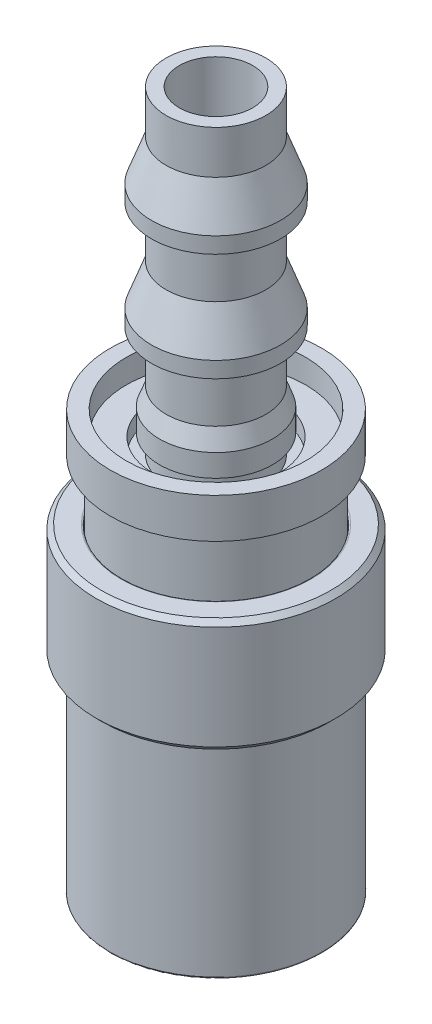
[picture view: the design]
ISO-10303-21;
HEADER;
FILE_DESCRIPTION(('STEP AP214'),'2;1');
FILE_NAME('part.step','',(''),(''),'','','');
FILE_SCHEMA(('AUTOMOTIVE_DESIGN { 1 0 10303 214 1 1 1 1 }'));
ENDSEC;
DATA;
#1=APPLICATION_CONTEXT('core data for automotive mechanical design processes');
#2=APPLICATION_PROTOCOL_DEFINITION('international standard','automotive_design',2000,#1);
#3=PRODUCT_CONTEXT('',#1,'mechanical');
#4=PRODUCT('Part','Part','',(#3));
#5=PRODUCT_RELATED_PRODUCT_CATEGORY('part','',(#4));
#6=PRODUCT_DEFINITION_FORMATION('','',#4);
#7=PRODUCT_DEFINITION_CONTEXT('part definition',#1,'design');
#8=PRODUCT_DEFINITION('design','',#6,#7);
#9=PRODUCT_DEFINITION_SHAPE('','',#8);
#10=(LENGTH_UNIT() NAMED_UNIT(*) SI_UNIT(.MILLI.,.METRE.));
#11=(NAMED_UNIT(*) PLANE_ANGLE_UNIT() SI_UNIT($,.RADIAN.));
#12=(NAMED_UNIT(*) SI_UNIT($,.STERADIAN.) SOLID_ANGLE_UNIT());
#13=UNCERTAINTY_MEASURE_WITH_UNIT(LENGTH_MEASURE(1.E-05),#10,'distance_accuracy_value','');
#14=(GEOMETRIC_REPRESENTATION_CONTEXT(3) GLOBAL_UNCERTAINTY_ASSIGNED_CONTEXT((#13)) GLOBAL_UNIT_ASSIGNED_CONTEXT((#10,
#11,#12)) REPRESENTATION_CONTEXT('',''));
#15=CARTESIAN_POINT('',(0.,0.,0.));
#16=DIRECTION('',(0.,0.,1.));
#17=DIRECTION('',(1.,0.,0.));
#18=AXIS2_PLACEMENT_3D('',#15,#16,#17);
#19=CARTESIAN_POINT('',(0.,31.4198,-8.1915));
#20=DIRECTION('',(0.,1.,0.));
#21=DIRECTION('',(1.,0.,0.));
#22=AXIS2_PLACEMENT_3D('',#19,#20,#21);
#23=PLANE('',#22);
#24=CARTESIAN_POINT('',(0.,31.4198,0.));
#25=DIRECTION('',(0.,-1.,0.));
#26=DIRECTION('',(1.,0.,0.));
#27=AXIS2_PLACEMENT_3D('',#24,#25,#26);
#28=CIRCLE('',#27,5.0165);
#29=CARTESIAN_POINT('',(0.,31.4198,-5.0165));
#30=VERTEX_POINT('',#29);
#31=CARTESIAN_POINT('',(0.,31.4198,5.0165));
#32=VERTEX_POINT('',#31);
#33=EDGE_CURVE('P0_E47',#30,#32,#28,.T.);
#34=ORIENTED_EDGE('',*,*,#33,.T.);
#35=CARTESIAN_POINT('',(0.,31.4198,0.));
#36=DIRECTION('',(0.,-1.,0.));
#37=DIRECTION('',(1.,0.,0.));
#38=AXIS2_PLACEMENT_3D('',#35,#36,#37);
#39=CIRCLE('',#38,5.0165);
#40=EDGE_CURVE('P0_E54',#32,#30,#39,.T.);
#41=ORIENTED_EDGE('',*,*,#40,.T.);
#42=EDGE_LOOP('',(#34,#41));
#43=FACE_BOUND('',#42,.T.);
#44=CARTESIAN_POINT('',(0.,31.4198,0.));
#45=DIRECTION('',(0.,1.,0.));
#46=DIRECTION('',(0.,0.,1.));
#47=AXIS2_PLACEMENT_3D('',#44,#45,#46);
#48=CIRCLE('',#47,7.14375);
#49=CARTESIAN_POINT('',(0.,31.4198,7.14375));
#50=VERTEX_POINT('',#49);
#51=EDGE_CURVE('P0_E11',#50,#50,#48,.F.);
#52=ORIENTED_EDGE('',*,*,#51,.F.);
#53=EDGE_LOOP('',(#52));
#54=FACE_BOUND('',#53,.T.);
#55=ADVANCED_FACE('P0_F16',(#43,#54),#23,.T.);
#56=CARTESIAN_POINT('',(0.,30.1498,-5.0165));
#57=DIRECTION('',(0.,-1.,0.));
#58=DIRECTION('',(0.,0.,-1.));
#59=AXIS2_PLACEMENT_3D('',#56,#57,#58);
#60=PLANE('',#59);
#61=CARTESIAN_POINT('',(0.,30.1498,0.));
#62=DIRECTION('',(0.,-1.,0.));
#63=DIRECTION('',(1.,0.,0.));
#64=AXIS2_PLACEMENT_3D('',#61,#62,#63);
#65=CIRCLE('',#64,5.0165);
#66=CARTESIAN_POINT('',(0.,30.1498,-5.0165));
#67=VERTEX_POINT('',#66);
#68=CARTESIAN_POINT('',(0.,30.1498,5.0165));
#69=VERTEX_POINT('',#68);
#70=EDGE_CURVE('P0_E25',#67,#69,#65,.T.);
#71=ORIENTED_EDGE('',*,*,#70,.F.);
#72=CARTESIAN_POINT('',(0.,30.1498,0.));
#73=DIRECTION('',(0.,-1.,0.));
#74=DIRECTION('',(1.,0.,0.));
#75=AXIS2_PLACEMENT_3D('',#72,#73,#74);
#76=CIRCLE('',#75,5.0165);
#77=EDGE_CURVE('P0_E56',#69,#67,#76,.T.);
#78=ORIENTED_EDGE('',*,*,#77,.F.);
#79=EDGE_LOOP('',(#71,#78));
#80=FACE_BOUND('',#79,.T.);
#81=CARTESIAN_POINT('',(0.,30.1498,0.));
#82=DIRECTION('',(0.,1.,0.));
#83=DIRECTION('',(0.,0.,1.));
#84=AXIS2_PLACEMENT_3D('',#81,#82,#83);
#85=CIRCLE('',#84,8.41375);
#86=CARTESIAN_POINT('',(0.,30.1498,8.41375));
#87=VERTEX_POINT('',#86);
#88=EDGE_CURVE('P0_E63',#87,#87,#85,.T.);
#89=ORIENTED_EDGE('',*,*,#88,.F.);
#90=EDGE_LOOP('',(#89));
#91=FACE_BOUND('',#90,.T.);
#92=ADVANCED_FACE('P0_F96',(#80,#91),#60,.T.);
#93=CARTESIAN_POINT('',(0.,30.7848,0.));
#94=DIRECTION('',(0.,-1.,0.));
#95=DIRECTION('',(0.,0.,-1.));
#96=AXIS2_PLACEMENT_3D('',#93,#94,#95);
#97=CYLINDRICAL_SURFACE('',#96,5.0165);
#98=ORIENTED_EDGE('',*,*,#70,.T.);
#99=DIRECTION('',(0.,1.,0.));
#100=VECTOR('',#99,1.);
#101=CARTESIAN_POINT('',(0.,30.7848,5.0165));
#102=LINE('',#101,#100);
#103=EDGE_CURVE('P0_E59',#69,#32,#102,.T.);
#104=ORIENTED_EDGE('',*,*,#103,.T.);
#105=ORIENTED_EDGE('',*,*,#33,.F.);
#106=ORIENTED_EDGE('',*,*,#40,.F.);
#107=ORIENTED_EDGE('',*,*,#103,.F.);
#108=ORIENTED_EDGE('',*,*,#77,.T.);
#109=EDGE_LOOP('',(#98,#104,#105,#106,#107,#108));
#110=FACE_BOUND('',#109,.T.);
#111=ADVANCED_FACE('P0_F18',(#110),#97,.F.);
#112=CARTESIAN_POINT('',(0.,37.4364687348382,0.));
#113=DIRECTION('',(0.,1.,0.));
#114=DIRECTION('',(0.,0.,1.));
#115=AXIS2_PLACEMENT_3D('',#112,#113,#114);
#116=CYLINDRICAL_SURFACE('',#115,8.41375);
#117=ORIENTED_EDGE('',*,*,#88,.T.);
#118=EDGE_LOOP('',(#117));
#119=FACE_BOUND('',#118,.T.);
#120=CARTESIAN_POINT('',(0.,33.3248,0.));
#121=DIRECTION('',(0.,1.,0.));
#122=DIRECTION('',(0.,0.,1.));
#123=AXIS2_PLACEMENT_3D('',#120,#121,#122);
#124=CIRCLE('',#123,8.41375);
#125=CARTESIAN_POINT('',(0.,33.3248,8.41375));
#126=VERTEX_POINT('',#125);
#127=EDGE_CURVE('P0_E67',#126,#126,#124,.T.);
#128=ORIENTED_EDGE('',*,*,#127,.F.);
#129=EDGE_LOOP('',(#128));
#130=FACE_BOUND('',#129,.T.);
#131=ADVANCED_FACE('P0_F84',(#119,#130),#116,.T.);
#132=CARTESIAN_POINT('',(-8.41375,33.3248,0.));
#133=DIRECTION('',(0.,1.,0.));
#134=DIRECTION('',(0.,0.,1.));
#135=AXIS2_PLACEMENT_3D('',#132,#133,#134);
#136=PLANE('',#135);
#137=ORIENTED_EDGE('',*,*,#127,.T.);
#138=EDGE_LOOP('',(#137));
#139=FACE_BOUND('',#138,.T.);
#140=CARTESIAN_POINT('',(0.,33.3248,0.));
#141=DIRECTION('',(0.,1.,0.));
#142=DIRECTION('',(0.,0.,1.));
#143=AXIS2_PLACEMENT_3D('',#140,#141,#142);
#144=CIRCLE('',#143,7.14375);
#145=CARTESIAN_POINT('',(0.,33.3248,7.14375));
#146=VERTEX_POINT('',#145);
#147=EDGE_CURVE('P0_E75',#146,#146,#144,.T.);
#148=ORIENTED_EDGE('',*,*,#147,.F.);
#149=EDGE_LOOP('',(#148));
#150=FACE_BOUND('',#149,.T.);
#151=ADVANCED_FACE('P0_F82',(#139,#150),#136,.T.);
#152=CARTESIAN_POINT('',(0.,37.4364687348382,0.));
#153=DIRECTION('',(0.,1.,0.));
#154=DIRECTION('',(0.,0.,1.));
#155=AXIS2_PLACEMENT_3D('',#152,#153,#154);
#156=CYLINDRICAL_SURFACE('',#155,7.14375);
#157=ORIENTED_EDGE('',*,*,#147,.T.);
#158=EDGE_LOOP('',(#157));
#159=FACE_BOUND('',#158,.T.);
#160=ORIENTED_EDGE('',*,*,#51,.T.);
#161=EDGE_LOOP('',(#160));
#162=FACE_BOUND('',#161,.T.);
#163=ADVANCED_FACE('P0_F79',(#159,#162),#156,.F.);
#164=CLOSED_SHELL('',(#55,#92,#111,#131,#151,#163));
#165=MANIFOLD_SOLID_BREP('P0_B1',#164);
#166=CARTESIAN_POINT('',(0.,0.254,0.));
#167=DIRECTION('',(0.,1.,0.));
#168=DIRECTION('',(0.,0.,1.));
#169=AXIS2_PLACEMENT_3D('',#166,#167,#168);
#170=TOROIDAL_SURFACE('',#169,6.096,0.254);
#171=CARTESIAN_POINT('',(0.,0.254,0.));
#172=DIRECTION('',(0.,-1.,0.));
#173=DIRECTION('',(0.,0.,-1.));
#174=AXIS2_PLACEMENT_3D('',#171,#172,#173);
#175=CIRCLE('',#174,6.35);
#176=CARTESIAN_POINT('',(0.,0.254,6.35));
#177=VERTEX_POINT('',#176);
#178=CARTESIAN_POINT('',(0.,0.254,-6.35));
#179=VERTEX_POINT('',#178);
#180=EDGE_CURVE('P1_E11',#177,#179,#175,.T.);
#181=ORIENTED_EDGE('',*,*,#180,.T.);
#182=CARTESIAN_POINT('',(0.,0.254,-6.096));
#183=DIRECTION('',(-1.,0.,0.));
#184=DIRECTION('',(0.,0.,-1.));
#185=AXIS2_PLACEMENT_3D('',#182,#183,#184);
#186=CIRCLE('',#185,0.254);
#187=CARTESIAN_POINT('',(0.,0.,-6.096));
#188=VERTEX_POINT('',#187);
#189=EDGE_CURVE('P1_E27',#179,#188,#186,.T.);
#190=ORIENTED_EDGE('',*,*,#189,.T.);
#191=CARTESIAN_POINT('',(0.,0.,0.));
#192=DIRECTION('',(0.,1.,0.));
#193=DIRECTION('',(0.,0.,-1.));
#194=AXIS2_PLACEMENT_3D('',#191,#192,#193);
#195=CIRCLE('',#194,6.096);
#196=CARTESIAN_POINT('',(0.,0.,6.096));
#197=VERTEX_POINT('',#196);
#198=EDGE_CURVE('P1_E196',#188,#197,#195,.T.);
#199=ORIENTED_EDGE('',*,*,#198,.T.);
#200=CARTESIAN_POINT('',(0.,0.,0.));
#201=DIRECTION('',(0.,1.,0.));
#202=DIRECTION('',(0.,0.,-1.));
#203=AXIS2_PLACEMENT_3D('',#200,#201,#202);
#204=CIRCLE('',#203,6.096);
#205=EDGE_CURVE('P1_E190',#197,#188,#204,.T.);
#206=ORIENTED_EDGE('',*,*,#205,.T.);
#207=ORIENTED_EDGE('',*,*,#189,.F.);
#208=CARTESIAN_POINT('',(0.,0.254,0.));
#209=DIRECTION('',(0.,-1.,0.));
#210=DIRECTION('',(0.,0.,-1.));
#211=AXIS2_PLACEMENT_3D('',#208,#209,#210);
#212=CIRCLE('',#211,6.35);
#213=EDGE_CURVE('P1_E183',#179,#177,#212,.T.);
#214=ORIENTED_EDGE('',*,*,#213,.T.);
#215=EDGE_LOOP('',(#181,#190,#199,#206,#207,#214));
#216=FACE_BOUND('',#215,.T.);
#217=ADVANCED_FACE('P1_F16',(#216),#170,.T.);
#218=CARTESIAN_POINT('',(0.,0.,6.35));
#219=DIRECTION('',(0.,-1.,0.));
#220=DIRECTION('',(0.,0.,-1.));
#221=AXIS2_PLACEMENT_3D('',#218,#219,#220);
#222=PLANE('',#221);
#223=ORIENTED_EDGE('',*,*,#205,.F.);
#224=ORIENTED_EDGE('',*,*,#198,.F.);
#225=EDGE_LOOP('',(#223,#224));
#226=FACE_BOUND('',#225,.T.);
#227=CARTESIAN_POINT('',(0.,0.,0.));
#228=DIRECTION('',(0.,-1.,0.));
#229=DIRECTION('',(0.,0.,-1.));
#230=AXIS2_PLACEMENT_3D('',#227,#228,#229);
#231=CIRCLE('',#230,5.5626);
#232=CARTESIAN_POINT('',(0.,0.,5.5626));
#233=VERTEX_POINT('',#232);
#234=EDGE_CURVE('P1_E20',#233,#233,#231,.T.);
#235=ORIENTED_EDGE('',*,*,#234,.F.);
#236=EDGE_LOOP('',(#235));
#237=FACE_BOUND('',#236,.T.);
#238=ADVANCED_FACE('P1_F396',(#226,#237),#222,.T.);
#239=CARTESIAN_POINT('',(0.,7.62,0.));
#240=DIRECTION('',(0.,1.,0.));
#241=DIRECTION('',(0.,0.,1.));
#242=AXIS2_PLACEMENT_3D('',#239,#240,#241);
#243=CYLINDRICAL_SURFACE('',#242,6.35);
#244=CARTESIAN_POINT('',(0.,15.24,0.));
#245=DIRECTION('',(0.,1.,0.));
#246=DIRECTION('',(1.,0.,0.));
#247=AXIS2_PLACEMENT_3D('',#244,#245,#246);
#248=CIRCLE('',#247,6.35);
#249=CARTESIAN_POINT('',(0.,15.24,6.35));
#250=VERTEX_POINT('',#249);
#251=CARTESIAN_POINT('',(0.,15.24,-6.35));
#252=VERTEX_POINT('',#251);
#253=EDGE_CURVE('P1_E261',#250,#252,#248,.T.);
#254=ORIENTED_EDGE('',*,*,#253,.F.);
#255=CARTESIAN_POINT('',(0.,15.24,0.));
#256=DIRECTION('',(0.,1.,0.));
#257=DIRECTION('',(1.,0.,0.));
#258=AXIS2_PLACEMENT_3D('',#255,#256,#257);
#259=CIRCLE('',#258,6.35);
#260=EDGE_CURVE('P1_E199',#252,#250,#259,.T.);
#261=ORIENTED_EDGE('',*,*,#260,.F.);
#262=DIRECTION('',(0.,-1.,0.));
#263=VECTOR('',#262,1.);
#264=CARTESIAN_POINT('',(0.,7.62,-6.35));
#265=LINE('',#264,#263);
#266=EDGE_CURVE('P1_E187',#252,#179,#265,.T.);
#267=ORIENTED_EDGE('',*,*,#266,.T.);
#268=ORIENTED_EDGE('',*,*,#180,.F.);
#269=ORIENTED_EDGE('',*,*,#213,.F.);
#270=ORIENTED_EDGE('',*,*,#266,.F.);
#271=EDGE_LOOP('',(#254,#261,#267,#268,#269,#270));
#272=FACE_BOUND('',#271,.T.);
#273=ADVANCED_FACE('P1_F185',(#272),#243,.T.);
#274=CARTESIAN_POINT('',(0.,29.8958,0.));
#275=DIRECTION('',(0.,1.,0.));
#276=DIRECTION('',(0.,0.,1.));
#277=AXIS2_PLACEMENT_3D('',#274,#275,#276);
#278=TOROIDAL_SURFACE('',#277,7.1501,0.254);
#279=CARTESIAN_POINT('',(0.,30.1498,0.));
#280=DIRECTION('',(0.,-1.,0.));
#281=DIRECTION('',(0.,0.,-1.));
#282=AXIS2_PLACEMENT_3D('',#279,#280,#281);
#283=CIRCLE('',#282,7.1501);
#284=CARTESIAN_POINT('',(0.,30.1498,7.1501));
#285=VERTEX_POINT('',#284);
#286=CARTESIAN_POINT('',(0.,30.1498,-7.1501));
#287=VERTEX_POINT('',#286);
#288=EDGE_CURVE('P1_E202',#285,#287,#283,.T.);
#289=ORIENTED_EDGE('',*,*,#288,.T.);
#290=CARTESIAN_POINT('',(0.,29.8958,-7.1501));
#291=DIRECTION('',(-1.,0.,0.));
#292=DIRECTION('',(0.,0.,-1.));
#293=AXIS2_PLACEMENT_3D('',#290,#291,#292);
#294=CIRCLE('',#293,0.254);
#295=CARTESIAN_POINT('',(0.,29.8958,-7.4041));
#296=VERTEX_POINT('',#295);
#297=EDGE_CURVE('P1_E209',#287,#296,#294,.T.);
#298=ORIENTED_EDGE('',*,*,#297,.T.);
#299=CARTESIAN_POINT('',(0.,29.8958,0.));
#300=DIRECTION('',(0.,1.,0.));
#301=DIRECTION('',(0.,0.,-1.));
#302=AXIS2_PLACEMENT_3D('',#299,#300,#301);
#303=CIRCLE('',#302,7.4041);
#304=CARTESIAN_POINT('',(0.,29.8958,7.4041));
#305=VERTEX_POINT('',#304);
#306=EDGE_CURVE('P1_E241',#296,#305,#303,.T.);
#307=ORIENTED_EDGE('',*,*,#306,.T.);
#308=CARTESIAN_POINT('',(0.,29.8958,0.));
#309=DIRECTION('',(0.,1.,0.));
#310=DIRECTION('',(0.,0.,-1.));
#311=AXIS2_PLACEMENT_3D('',#308,#309,#310);
#312=CIRCLE('',#311,7.4041);
#313=EDGE_CURVE('P1_E245',#305,#296,#312,.T.);
#314=ORIENTED_EDGE('',*,*,#313,.T.);
#315=ORIENTED_EDGE('',*,*,#297,.F.);
#316=CARTESIAN_POINT('',(0.,30.1498,0.));
#317=DIRECTION('',(0.,-1.,0.));
#318=DIRECTION('',(0.,0.,-1.));
#319=AXIS2_PLACEMENT_3D('',#316,#317,#318);
#320=CIRCLE('',#319,7.1501);
#321=EDGE_CURVE('P1_E321',#287,#285,#320,.T.);
#322=ORIENTED_EDGE('',*,*,#321,.T.);
#323=EDGE_LOOP('',(#289,#298,#307,#314,#315,#322));
#324=FACE_BOUND('',#323,.T.);
#325=ADVANCED_FACE('P1_F405',(#324),#278,.T.);
#326=CARTESIAN_POINT('',(0.,22.6949,0.));
#327=DIRECTION('',(0.,1.,0.));
#328=DIRECTION('',(0.,0.,1.));
#329=AXIS2_PLACEMENT_3D('',#326,#327,#328);
#330=CYLINDRICAL_SURFACE('',#329,7.4041);
#331=DIRECTION('',(0.,-1.,0.));
#332=VECTOR('',#331,1.);
#333=CARTESIAN_POINT('',(0.,22.6949,-7.4041));
#334=LINE('',#333,#332);
#335=CARTESIAN_POINT('',(0.,28.1939996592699,-7.4041));
#336=VERTEX_POINT('',#335);
#337=EDGE_CURVE('P1_E40',#296,#336,#334,.T.);
#338=ORIENTED_EDGE('',*,*,#337,.T.);
#339=ORIENTED_EDGE('',*,*,#337,.F.);
#340=ORIENTED_EDGE('',*,*,#313,.F.);
#341=ORIENTED_EDGE('',*,*,#306,.F.);
#342=EDGE_LOOP('',(#338,#339,#340,#341));
#343=FACE_BOUND('',#342,.T.);
#344=DIRECTION('',(0.,-1.,0.));
#345=VECTOR('',#344,1.);
#346=CARTESIAN_POINT('',(0.,22.6949,-7.4041));
#347=LINE('',#346,#345);
#348=CARTESIAN_POINT('',(0.,25.3999996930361,-7.4041));
#349=VERTEX_POINT('',#348);
#350=CARTESIAN_POINT('',(0.,15.494,-7.4041));
#351=VERTEX_POINT('',#350);
#352=EDGE_CURVE('P1_E228',#349,#351,#347,.T.);
#353=ORIENTED_EDGE('',*,*,#352,.F.);
#354=ORIENTED_EDGE('',*,*,#352,.T.);
#355=CARTESIAN_POINT('',(0.,15.494,0.));
#356=DIRECTION('',(0.,-1.,0.));
#357=DIRECTION('',(0.,0.,-1.));
#358=AXIS2_PLACEMENT_3D('',#355,#356,#357);
#359=CIRCLE('',#358,7.4041);
#360=CARTESIAN_POINT('',(0.,15.494,7.4041));
#361=VERTEX_POINT('',#360);
#362=EDGE_CURVE('P1_E224',#361,#351,#359,.T.);
#363=ORIENTED_EDGE('',*,*,#362,.F.);
#364=CARTESIAN_POINT('',(0.,15.494,0.));
#365=DIRECTION('',(0.,-1.,0.));
#366=DIRECTION('',(0.,0.,-1.));
#367=AXIS2_PLACEMENT_3D('',#364,#365,#366);
#368=CIRCLE('',#367,7.4041);
#369=EDGE_CURVE('P1_E235',#351,#361,#368,.T.);
#370=ORIENTED_EDGE('',*,*,#369,.F.);
#371=EDGE_LOOP('',(#353,#354,#363,#370));
#372=FACE_BOUND('',#371,.T.);
#373=ADVANCED_FACE('P1_F440',(#343,#372),#330,.T.);
#374=CARTESIAN_POINT('',(0.,30.1498,4.9784));
#375=DIRECTION('',(0.,1.,0.));
#376=DIRECTION('',(1.,0.,0.));
#377=AXIS2_PLACEMENT_3D('',#374,#375,#376);
#378=PLANE('',#377);
#379=ORIENTED_EDGE('',*,*,#288,.F.);
#380=ORIENTED_EDGE('',*,*,#321,.F.);
#381=EDGE_LOOP('',(#379,#380));
#382=FACE_BOUND('',#381,.T.);
#383=CARTESIAN_POINT('',(0.,30.1498,0.));
#384=DIRECTION('',(0.,1.,0.));
#385=DIRECTION('',(-1.,0.,0.));
#386=AXIS2_PLACEMENT_3D('',#383,#384,#385);
#387=CIRCLE('',#386,3.96875);
#388=CARTESIAN_POINT('',(-3.96875,30.1498,0.));
#389=VERTEX_POINT('',#388);
#390=EDGE_CURVE('P1_E770',#389,#389,#387,.T.);
#391=ORIENTED_EDGE('',*,*,#390,.F.);
#392=EDGE_LOOP('',(#391));
#393=FACE_BOUND('',#392,.T.);
#394=ADVANCED_FACE('P1_F443',(#382,#393),#378,.T.);
#395=CARTESIAN_POINT('',(0.,15.494,0.));
#396=DIRECTION('',(0.,1.,0.));
#397=DIRECTION('',(0.,0.,1.));
#398=AXIS2_PLACEMENT_3D('',#395,#396,#397);
#399=TOROIDAL_SURFACE('',#398,7.1501,0.254);
#400=ORIENTED_EDGE('',*,*,#362,.T.);
#401=CARTESIAN_POINT('',(0.,15.494,-7.1501));
#402=DIRECTION('',(-1.,0.,0.));
#403=DIRECTION('',(0.,0.,-1.));
#404=AXIS2_PLACEMENT_3D('',#401,#402,#403);
#405=CIRCLE('',#404,0.254);
#406=CARTESIAN_POINT('',(0.,15.24,-7.1501));
#407=VERTEX_POINT('',#406);
#408=EDGE_CURVE('P1_E229',#351,#407,#405,.T.);
#409=ORIENTED_EDGE('',*,*,#408,.T.);
#410=CARTESIAN_POINT('',(0.,15.24,0.));
#411=DIRECTION('',(0.,1.,0.));
#412=DIRECTION('',(0.,0.,-1.));
#413=AXIS2_PLACEMENT_3D('',#410,#411,#412);
#414=CIRCLE('',#413,7.1501);
#415=CARTESIAN_POINT('',(0.,15.24,7.1501));
#416=VERTEX_POINT('',#415);
#417=EDGE_CURVE('P1_E234',#407,#416,#414,.T.);
#418=ORIENTED_EDGE('',*,*,#417,.T.);
#419=CARTESIAN_POINT('',(0.,15.24,0.));
#420=DIRECTION('',(0.,1.,0.));
#421=DIRECTION('',(0.,0.,-1.));
#422=AXIS2_PLACEMENT_3D('',#419,#420,#421);
#423=CIRCLE('',#422,7.1501);
#424=EDGE_CURVE('P1_E230',#416,#407,#423,.T.);
#425=ORIENTED_EDGE('',*,*,#424,.T.);
#426=ORIENTED_EDGE('',*,*,#408,.F.);
#427=ORIENTED_EDGE('',*,*,#369,.T.);
#428=EDGE_LOOP('',(#400,#409,#418,#425,#426,#427));
#429=FACE_BOUND('',#428,.T.);
#430=ADVANCED_FACE('P1_F444',(#429),#399,.T.);
#431=CARTESIAN_POINT('',(0.,15.24,7.4041));
#432=DIRECTION('',(0.,-1.,0.));
#433=DIRECTION('',(0.,0.,-1.));
#434=AXIS2_PLACEMENT_3D('',#431,#432,#433);
#435=PLANE('',#434);
#436=ORIENTED_EDGE('',*,*,#424,.F.);
#437=ORIENTED_EDGE('',*,*,#417,.F.);
#438=EDGE_LOOP('',(#436,#437));
#439=FACE_BOUND('',#438,.T.);
#440=ORIENTED_EDGE('',*,*,#253,.T.);
#441=ORIENTED_EDGE('',*,*,#260,.T.);
#442=EDGE_LOOP('',(#440,#441));
#443=FACE_BOUND('',#442,.T.);
#444=ADVANCED_FACE('P1_F18',(#439,#443),#435,.T.);
#445=CARTESIAN_POINT('',(0.,0.3937,0.));
#446=DIRECTION('',(0.,-1.,0.));
#447=DIRECTION('',(0.,0.,-1.));
#448=AXIS2_PLACEMENT_3D('',#445,#446,#447);
#449=CONICAL_SURFACE('',#448,5.1689,0.785398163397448);
#450=ORIENTED_EDGE('',*,*,#234,.T.);
#451=DIRECTION('',(0.,0.707106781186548,-0.707106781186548));
#452=VECTOR('',#451,1.);
#453=CARTESIAN_POINT('',(0.,0.3937,5.1689));
#454=LINE('',#453,#452);
#455=CARTESIAN_POINT('',(0.,0.7874,4.7752));
#456=VERTEX_POINT('',#455);
#457=EDGE_CURVE('P1_E316',#233,#456,#454,.T.);
#458=ORIENTED_EDGE('',*,*,#457,.T.);
#459=CARTESIAN_POINT('',(0.,0.7874,0.));
#460=DIRECTION('',(0.,1.,0.));
#461=DIRECTION('',(0.,0.,-1.));
#462=AXIS2_PLACEMENT_3D('',#459,#460,#461);
#463=CIRCLE('',#462,4.7752);
#464=CARTESIAN_POINT('',(0.,0.7874,-4.7752));
#465=VERTEX_POINT('',#464);
#466=EDGE_CURVE('P1_E311',#456,#465,#463,.T.);
#467=ORIENTED_EDGE('',*,*,#466,.T.);
#468=CARTESIAN_POINT('',(0.,0.7874,0.));
#469=DIRECTION('',(0.,1.,0.));
#470=DIRECTION('',(0.,0.,-1.));
#471=AXIS2_PLACEMENT_3D('',#468,#469,#470);
#472=CIRCLE('',#471,4.7752);
#473=EDGE_CURVE('P1_E307',#465,#456,#472,.T.);
#474=ORIENTED_EDGE('',*,*,#473,.T.);
#475=ORIENTED_EDGE('',*,*,#457,.F.);
#476=EDGE_LOOP('',(#450,#458,#467,#474,#475));
#477=FACE_BOUND('',#476,.T.);
#478=ADVANCED_FACE('P1_F393',(#477),#449,.F.);
#479=CARTESIAN_POINT('',(0.,4.05954416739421,0.));
#480=DIRECTION('',(0.,1.,0.));
#481=DIRECTION('',(0.,0.,1.));
#482=AXIS2_PLACEMENT_3D('',#479,#480,#481);
#483=CYLINDRICAL_SURFACE('',#482,4.7752);
#484=CARTESIAN_POINT('',(0.,8.11908833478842,0.));
#485=DIRECTION('',(0.,1.,0.));
#486=DIRECTION('',(1.,0.,0.));
#487=AXIS2_PLACEMENT_3D('',#484,#485,#486);
#488=CIRCLE('',#487,4.7752);
#489=CARTESIAN_POINT('',(0.,8.11908833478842,4.7752));
#490=VERTEX_POINT('',#489);
#491=CARTESIAN_POINT('',(0.,8.11908833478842,-4.7752));
#492=VERTEX_POINT('',#491);
#493=EDGE_CURVE('P1_E312',#490,#492,#488,.T.);
#494=ORIENTED_EDGE('',*,*,#493,.T.);
#495=DIRECTION('',(0.,-1.,0.));
#496=VECTOR('',#495,1.);
#497=CARTESIAN_POINT('',(0.,4.05954416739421,-4.7752));
#498=LINE('',#497,#496);
#499=EDGE_CURVE('P1_E213',#492,#465,#498,.T.);
#500=ORIENTED_EDGE('',*,*,#499,.T.);
#501=ORIENTED_EDGE('',*,*,#466,.F.);
#502=ORIENTED_EDGE('',*,*,#473,.F.);
#503=ORIENTED_EDGE('',*,*,#499,.F.);
#504=CARTESIAN_POINT('',(0.,8.11908833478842,0.));
#505=DIRECTION('',(0.,1.,0.));
#506=DIRECTION('',(1.,0.,0.));
#507=AXIS2_PLACEMENT_3D('',#504,#505,#506);
#508=CIRCLE('',#507,4.7752);
#509=EDGE_CURVE('P1_E248',#492,#490,#508,.T.);
#510=ORIENTED_EDGE('',*,*,#509,.T.);
#511=EDGE_LOOP('',(#494,#500,#501,#502,#503,#510));
#512=FACE_BOUND('',#511,.T.);
#513=ADVANCED_FACE('P1_F418',(#512),#483,.F.);
#514=CARTESIAN_POINT('',(0.,12.2174,0.));
#515=DIRECTION('',(0.,1.,0.));
#516=DIRECTION('',(0.,0.,1.));
#517=AXIS2_PLACEMENT_3D('',#514,#515,#516);
#518=CYLINDRICAL_SURFACE('',#517,5.0546);
#519=CARTESIAN_POINT('',(0.,12.8524,0.));
#520=DIRECTION('',(0.,1.,0.));
#521=DIRECTION('',(1.,0.,0.));
#522=AXIS2_PLACEMENT_3D('',#519,#520,#521);
#523=CIRCLE('',#522,5.0546);
#524=CARTESIAN_POINT('',(0.,12.8524,5.0546));
#525=VERTEX_POINT('',#524);
#526=CARTESIAN_POINT('',(0.,12.8524,-5.0546));
#527=VERTEX_POINT('',#526);
#528=EDGE_CURVE('P1_E223',#525,#527,#523,.T.);
#529=ORIENTED_EDGE('',*,*,#528,.T.);
#530=DIRECTION('',(0.,-1.,0.));
#531=VECTOR('',#530,1.);
#532=CARTESIAN_POINT('',(0.,12.2174,-5.0546));
#533=LINE('',#532,#531);
#534=CARTESIAN_POINT('',(0.,11.5824,-5.0546));
#535=VERTEX_POINT('',#534);
#536=EDGE_CURVE('P1_E218',#527,#535,#533,.T.);
#537=ORIENTED_EDGE('',*,*,#536,.T.);
#538=CARTESIAN_POINT('',(0.,11.5824,0.));
#539=DIRECTION('',(0.,1.,0.));
#540=DIRECTION('',(1.,0.,0.));
#541=AXIS2_PLACEMENT_3D('',#538,#539,#540);
#542=CIRCLE('',#541,5.0546);
#543=CARTESIAN_POINT('',(0.,11.5824,5.0546));
#544=VERTEX_POINT('',#543);
#545=EDGE_CURVE('P1_E219',#544,#535,#542,.T.);
#546=ORIENTED_EDGE('',*,*,#545,.F.);
#547=CARTESIAN_POINT('',(0.,11.5824,0.));
#548=DIRECTION('',(0.,1.,0.));
#549=DIRECTION('',(1.,0.,0.));
#550=AXIS2_PLACEMENT_3D('',#547,#548,#549);
#551=CIRCLE('',#550,5.0546);
#552=EDGE_CURVE('P1_E240',#535,#544,#551,.T.);
#553=ORIENTED_EDGE('',*,*,#552,.F.);
#554=ORIENTED_EDGE('',*,*,#536,.F.);
#555=CARTESIAN_POINT('',(0.,12.8524,0.));
#556=DIRECTION('',(0.,1.,0.));
#557=DIRECTION('',(1.,0.,0.));
#558=AXIS2_PLACEMENT_3D('',#555,#556,#557);
#559=CIRCLE('',#558,5.0546);
#560=EDGE_CURVE('P1_E215',#527,#525,#559,.T.);
#561=ORIENTED_EDGE('',*,*,#560,.T.);
#562=EDGE_LOOP('',(#529,#537,#546,#553,#554,#561));
#563=FACE_BOUND('',#562,.T.);
#564=ADVANCED_FACE('P1_F274',(#563),#518,.F.);
#565=CARTESIAN_POINT('',(0.,11.4650824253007,0.));
#566=DIRECTION('',(0.,-1.,0.));
#567=DIRECTION('',(0.,0.,1.));
#568=AXIS2_PLACEMENT_3D('',#565,#566,#567);
#569=CONICAL_SURFACE('',#568,5.2578,1.04719755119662);
#570=ORIENTED_EDGE('',*,*,#545,.T.);
#571=DIRECTION('',(0.,-0.499999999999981,-0.86602540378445));
#572=VECTOR('',#571,1.);
#573=CARTESIAN_POINT('',(0.,11.4650824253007,-5.2578));
#574=LINE('',#573,#572);
#575=CARTESIAN_POINT('',(0.,11.3477648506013,-5.461));
#576=VERTEX_POINT('',#575);
#577=EDGE_CURVE('P1_E236',#535,#576,#574,.T.);
#578=ORIENTED_EDGE('',*,*,#577,.T.);
#579=CARTESIAN_POINT('',(0.,11.3477648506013,0.));
#580=DIRECTION('',(0.,1.,0.));
#581=DIRECTION('',(1.,0.,0.));
#582=AXIS2_PLACEMENT_3D('',#579,#580,#581);
#583=CIRCLE('',#582,5.461);
#584=CARTESIAN_POINT('',(0.,11.3477648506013,5.461));
#585=VERTEX_POINT('',#584);
#586=EDGE_CURVE('P1_E279',#585,#576,#583,.T.);
#587=ORIENTED_EDGE('',*,*,#586,.F.);
#588=CARTESIAN_POINT('',(0.,11.3477648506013,0.));
#589=DIRECTION('',(0.,1.,0.));
#590=DIRECTION('',(1.,0.,0.));
#591=AXIS2_PLACEMENT_3D('',#588,#589,#590);
#592=CIRCLE('',#591,5.461);
#593=EDGE_CURVE('P1_E277',#576,#585,#592,.T.);
#594=ORIENTED_EDGE('',*,*,#593,.F.);
#595=ORIENTED_EDGE('',*,*,#577,.F.);
#596=ORIENTED_EDGE('',*,*,#552,.T.);
#597=EDGE_LOOP('',(#570,#578,#587,#594,#595,#596));
#598=FACE_BOUND('',#597,.T.);
#599=ADVANCED_FACE('P1_F270',(#598),#569,.F.);
#600=CARTESIAN_POINT('',(0.,10.3952648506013,0.));
#601=DIRECTION('',(0.,1.,0.));
#602=DIRECTION('',(0.,0.,1.));
#603=AXIS2_PLACEMENT_3D('',#600,#601,#602);
#604=CYLINDRICAL_SURFACE('',#603,5.461);
#605=ORIENTED_EDGE('',*,*,#586,.T.);
#606=DIRECTION('',(0.,-1.,0.));
#607=VECTOR('',#606,1.);
#608=CARTESIAN_POINT('',(0.,10.3952648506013,-5.461));
#609=LINE('',#608,#607);
#610=CARTESIAN_POINT('',(0.,9.44276485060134,-5.461));
#611=VERTEX_POINT('',#610);
#612=EDGE_CURVE('P1_E282',#576,#611,#609,.T.);
#613=ORIENTED_EDGE('',*,*,#612,.T.);
#614=CARTESIAN_POINT('',(0.,9.44276485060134,0.));
#615=DIRECTION('',(0.,1.,0.));
#616=DIRECTION('',(1.,0.,0.));
#617=AXIS2_PLACEMENT_3D('',#614,#615,#616);
#618=CIRCLE('',#617,5.461);
#619=CARTESIAN_POINT('',(0.,9.44276485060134,5.461));
#620=VERTEX_POINT('',#619);
#621=EDGE_CURVE('P1_E283',#620,#611,#618,.T.);
#622=ORIENTED_EDGE('',*,*,#621,.F.);
#623=CARTESIAN_POINT('',(0.,9.44276485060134,0.));
#624=DIRECTION('',(0.,1.,0.));
#625=DIRECTION('',(1.,0.,0.));
#626=AXIS2_PLACEMENT_3D('',#623,#624,#625);
#627=CIRCLE('',#626,5.461);
#628=EDGE_CURVE('P1_E303',#611,#620,#627,.T.);
#629=ORIENTED_EDGE('',*,*,#628,.F.);
#630=ORIENTED_EDGE('',*,*,#612,.F.);
#631=ORIENTED_EDGE('',*,*,#593,.T.);
#632=EDGE_LOOP('',(#605,#613,#622,#629,#630,#631));
#633=FACE_BOUND('',#632,.T.);
#634=ADVANCED_FACE('P1_F286',(#633),#604,.F.);
#635=CARTESIAN_POINT('',(0.,9.325447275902,0.));
#636=DIRECTION('',(0.,1.,0.));
#637=DIRECTION('',(0.,0.,1.));
#638=AXIS2_PLACEMENT_3D('',#635,#636,#637);
#639=CONICAL_SURFACE('',#638,5.2578,1.04719755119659);
#640=ORIENTED_EDGE('',*,*,#621,.T.);
#641=DIRECTION('',(0.,-0.500000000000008,0.866025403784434));
#642=VECTOR('',#641,1.);
#643=CARTESIAN_POINT('',(0.,9.325447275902,-5.2578));
#644=LINE('',#643,#642);
#645=CARTESIAN_POINT('',(0.,9.20812970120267,-5.0546));
#646=VERTEX_POINT('',#645);
#647=EDGE_CURVE('P1_E339',#611,#646,#644,.T.);
#648=ORIENTED_EDGE('',*,*,#647,.T.);
#649=CARTESIAN_POINT('',(0.,9.20812970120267,0.));
#650=DIRECTION('',(0.,1.,0.));
#651=DIRECTION('',(1.,0.,0.));
#652=AXIS2_PLACEMENT_3D('',#649,#650,#651);
#653=CIRCLE('',#652,5.0546);
#654=CARTESIAN_POINT('',(0.,9.20812970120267,5.0546));
#655=VERTEX_POINT('',#654);
#656=EDGE_CURVE('P1_E300',#655,#646,#653,.T.);
#657=ORIENTED_EDGE('',*,*,#656,.F.);
#658=CARTESIAN_POINT('',(0.,9.20812970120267,0.));
#659=DIRECTION('',(0.,1.,0.));
#660=DIRECTION('',(1.,0.,0.));
#661=AXIS2_PLACEMENT_3D('',#658,#659,#660);
#662=CIRCLE('',#661,5.0546);
#663=EDGE_CURVE('P1_E330',#646,#655,#662,.T.);
#664=ORIENTED_EDGE('',*,*,#663,.F.);
#665=ORIENTED_EDGE('',*,*,#647,.F.);
#666=ORIENTED_EDGE('',*,*,#628,.T.);
#667=EDGE_LOOP('',(#640,#648,#657,#664,#665,#666));
#668=FACE_BOUND('',#667,.T.);
#669=ADVANCED_FACE('P1_F456',(#668),#639,.F.);
#670=CARTESIAN_POINT('',(0.,8.74426485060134,0.));
#671=DIRECTION('',(0.,1.,0.));
#672=DIRECTION('',(0.,0.,1.));
#673=AXIS2_PLACEMENT_3D('',#670,#671,#672);
#674=CYLINDRICAL_SURFACE('',#673,5.0546);
#675=ORIENTED_EDGE('',*,*,#656,.T.);
#676=DIRECTION('',(0.,-1.,0.));
#677=VECTOR('',#676,1.);
#678=CARTESIAN_POINT('',(0.,8.74426485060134,-5.0546));
#679=LINE('',#678,#677);
#680=CARTESIAN_POINT('',(0.,8.2804,-5.0546));
#681=VERTEX_POINT('',#680);
#682=EDGE_CURVE('P1_E304',#646,#681,#679,.T.);
#683=ORIENTED_EDGE('',*,*,#682,.T.);
#684=CARTESIAN_POINT('',(0.,8.2804,0.));
#685=DIRECTION('',(0.,1.,0.));
#686=DIRECTION('',(1.,0.,0.));
#687=AXIS2_PLACEMENT_3D('',#684,#685,#686);
#688=CIRCLE('',#687,5.0546);
#689=CARTESIAN_POINT('',(0.,8.2804,5.0546));
#690=VERTEX_POINT('',#689);
#691=EDGE_CURVE('P1_E147',#690,#681,#688,.T.);
#692=ORIENTED_EDGE('',*,*,#691,.F.);
#693=CARTESIAN_POINT('',(0.,8.2804,0.));
#694=DIRECTION('',(0.,1.,0.));
#695=DIRECTION('',(1.,0.,0.));
#696=AXIS2_PLACEMENT_3D('',#693,#694,#695);
#697=CIRCLE('',#696,5.0546);
#698=EDGE_CURVE('P1_E155',#681,#690,#697,.T.);
#699=ORIENTED_EDGE('',*,*,#698,.F.);
#700=ORIENTED_EDGE('',*,*,#682,.F.);
#701=ORIENTED_EDGE('',*,*,#663,.T.);
#702=EDGE_LOOP('',(#675,#683,#692,#699,#700,#701));
#703=FACE_BOUND('',#702,.T.);
#704=ADVANCED_FACE('P1_F458',(#703),#674,.F.);
#705=CARTESIAN_POINT('',(0.,8.19974416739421,0.));
#706=DIRECTION('',(0.,1.,0.));
#707=DIRECTION('',(0.,0.,1.));
#708=AXIS2_PLACEMENT_3D('',#705,#706,#707);
#709=CONICAL_SURFACE('',#708,4.9149,1.04719755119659);
#710=ORIENTED_EDGE('',*,*,#691,.T.);
#711=DIRECTION('',(0.,-0.5,0.866025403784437));
#712=VECTOR('',#711,1.);
#713=CARTESIAN_POINT('',(0.,8.19974416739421,-4.9149));
#714=LINE('',#713,#712);
#715=EDGE_CURVE('P1_E263',#681,#492,#714,.T.);
#716=ORIENTED_EDGE('',*,*,#715,.T.);
#717=ORIENTED_EDGE('',*,*,#493,.F.);
#718=ORIENTED_EDGE('',*,*,#509,.F.);
#719=ORIENTED_EDGE('',*,*,#715,.F.);
#720=ORIENTED_EDGE('',*,*,#698,.T.);
#721=EDGE_LOOP('',(#710,#716,#717,#718,#719,#720));
#722=FACE_BOUND('',#721,.T.);
#723=ADVANCED_FACE('P1_F410',(#722),#709,.F.);
#724=CARTESIAN_POINT('',(0.,19.9136,0.));
#725=DIRECTION('',(0.,1.,0.));
#726=DIRECTION('',(0.,0.,1.));
#727=AXIS2_PLACEMENT_3D('',#724,#725,#726);
#728=CYLINDRICAL_SURFACE('',#727,3.3782);
#729=CARTESIAN_POINT('',(0.,26.9748,0.));
#730=DIRECTION('',(0.,1.,0.));
#731=DIRECTION('',(1.,0.,0.));
#732=AXIS2_PLACEMENT_3D('',#729,#730,#731);
#733=CIRCLE('',#732,3.3782);
#734=CARTESIAN_POINT('',(0.,26.9748,-3.3782));
#735=VERTEX_POINT('',#734);
#736=EDGE_CURVE('P1_E254',#735,#735,#733,.T.);
#737=ORIENTED_EDGE('',*,*,#736,.T.);
#738=DIRECTION('',(0.,-1.,0.));
#739=VECTOR('',#738,1.);
#740=CARTESIAN_POINT('',(0.,19.9136,-3.3782));
#741=LINE('',#740,#739);
#742=CARTESIAN_POINT('',(0.,12.8524,-3.3782));
#743=VERTEX_POINT('',#742);
#744=EDGE_CURVE('P1_E250',#735,#743,#741,.T.);
#745=ORIENTED_EDGE('',*,*,#744,.T.);
#746=CARTESIAN_POINT('',(0.,12.8524,0.));
#747=DIRECTION('',(0.,1.,0.));
#748=DIRECTION('',(1.,0.,0.));
#749=AXIS2_PLACEMENT_3D('',#746,#747,#748);
#750=CIRCLE('',#749,3.3782);
#751=CARTESIAN_POINT('',(0.,12.8524,3.3782));
#752=VERTEX_POINT('',#751);
#753=EDGE_CURVE('P1_E255',#752,#743,#750,.T.);
#754=ORIENTED_EDGE('',*,*,#753,.F.);
#755=CARTESIAN_POINT('',(0.,12.8524,0.));
#756=DIRECTION('',(0.,1.,0.));
#757=DIRECTION('',(1.,0.,0.));
#758=AXIS2_PLACEMENT_3D('',#755,#756,#757);
#759=CIRCLE('',#758,3.3782);
#760=EDGE_CURVE('P1_E340',#743,#752,#759,.T.);
#761=ORIENTED_EDGE('',*,*,#760,.F.);
#762=ORIENTED_EDGE('',*,*,#744,.F.);
#763=EDGE_LOOP('',(#737,#745,#754,#761,#762));
#764=FACE_BOUND('',#763,.T.);
#765=ADVANCED_FACE('P1_F412',(#764),#728,.F.);
#766=CARTESIAN_POINT('',(0.,12.8524,5.0546));
#767=DIRECTION('',(0.,-1.,0.));
#768=DIRECTION('',(0.,0.,-1.));
#769=AXIS2_PLACEMENT_3D('',#766,#767,#768);
#770=PLANE('',#769);
#771=ORIENTED_EDGE('',*,*,#528,.F.);
#772=ORIENTED_EDGE('',*,*,#560,.F.);
#773=EDGE_LOOP('',(#771,#772));
#774=FACE_BOUND('',#773,.T.);
#775=ORIENTED_EDGE('',*,*,#753,.T.);
#776=ORIENTED_EDGE('',*,*,#760,.T.);
#777=EDGE_LOOP('',(#775,#776));
#778=FACE_BOUND('',#777,.T.);
#779=ADVANCED_FACE('P1_F415',(#774,#778),#770,.T.);
#780=CARTESIAN_POINT('',(-4.4918465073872,31.7246,0.));
#781=DIRECTION('',(0.,1.,0.));
#782=DIRECTION('',(-1.,0.,0.));
#783=AXIS2_PLACEMENT_3D('',#780,#781,#782);
#784=PLANE('',#783);
#785=CARTESIAN_POINT('',(0.,31.7246,0.));
#786=DIRECTION('',(0.,1.,0.));
#787=DIRECTION('',(-1.,0.,0.));
#788=AXIS2_PLACEMENT_3D('',#785,#786,#787);
#789=CIRCLE('',#788,4.4918465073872);
#790=CARTESIAN_POINT('',(-4.49184650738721,31.7246,0.));
#791=VERTEX_POINT('',#790);
#792=EDGE_CURVE('P1_E776',#791,#791,#789,.T.);
#793=ORIENTED_EDGE('',*,*,#792,.F.);
#794=EDGE_LOOP('',(#793));
#795=FACE_BOUND('',#794,.T.);
#796=CARTESIAN_POINT('',(0.,31.7246,0.));
#797=DIRECTION('',(0.,1.,0.));
#798=DIRECTION('',(-1.,0.,0.));
#799=AXIS2_PLACEMENT_3D('',#796,#797,#798);
#800=CIRCLE('',#799,3.96875);
#801=CARTESIAN_POINT('',(-3.96875,31.7246,0.));
#802=VERTEX_POINT('',#801);
#803=EDGE_CURVE('P1_E772',#802,#802,#800,.T.);
#804=ORIENTED_EDGE('',*,*,#803,.T.);
#805=EDGE_LOOP('',(#804));
#806=FACE_BOUND('',#805,.T.);
#807=ADVANCED_FACE('P1_F431',(#795,#806),#784,.F.);
#808=CARTESIAN_POINT('',(0.,55.5498,0.));
#809=DIRECTION('',(0.,1.,0.));
#810=DIRECTION('',(-1.,0.,0.));
#811=AXIS2_PLACEMENT_3D('',#808,#809,#810);
#812=CYLINDRICAL_SURFACE('',#811,3.96875);
#813=ORIENTED_EDGE('',*,*,#803,.F.);
#814=EDGE_LOOP('',(#813));
#815=FACE_BOUND('',#814,.T.);
#816=ORIENTED_EDGE('',*,*,#390,.T.);
#817=EDGE_LOOP('',(#816));
#818=FACE_BOUND('',#817,.T.);
#819=ADVANCED_FACE('P1_F495',(#815,#818),#812,.T.);
#820=CARTESIAN_POINT('',(0.,55.5498,0.));
#821=DIRECTION('',(0.,1.,0.));
#822=DIRECTION('',(-1.,0.,0.));
#823=AXIS2_PLACEMENT_3D('',#820,#821,#822);
#824=CYLINDRICAL_SURFACE('',#823,4.4918465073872);
#825=CARTESIAN_POINT('',(0.,33.5026,0.));
#826=DIRECTION('',(0.,1.,0.));
#827=DIRECTION('',(-1.,0.,0.));
#828=AXIS2_PLACEMENT_3D('',#825,#826,#827);
#829=CIRCLE('',#828,4.4918465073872);
#830=CARTESIAN_POINT('',(-4.49184650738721,33.5026,0.));
#831=VERTEX_POINT('',#830);
#832=EDGE_CURVE('P1_E785',#831,#831,#829,.T.);
#833=ORIENTED_EDGE('',*,*,#832,.F.);
#834=EDGE_LOOP('',(#833));
#835=FACE_BOUND('',#834,.T.);
#836=ORIENTED_EDGE('',*,*,#792,.T.);
#837=EDGE_LOOP('',(#836));
#838=FACE_BOUND('',#837,.T.);
#839=ADVANCED_FACE('P1_F504',(#835,#838),#824,.T.);
#840=CARTESIAN_POINT('',(0.,33.5026,0.));
#841=DIRECTION('',(0.,-1.,0.));
#842=DIRECTION('',(1.,0.,0.));
#843=AXIS2_PLACEMENT_3D('',#840,#841,#842);
#844=CONICAL_SURFACE('',#843,4.4918465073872,0.348153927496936);
#845=CARTESIAN_POINT('',(0.,34.9438839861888,0.));
#846=DIRECTION('',(0.,1.,0.));
#847=DIRECTION('',(-1.,0.,0.));
#848=AXIS2_PLACEMENT_3D('',#845,#846,#847);
#849=CIRCLE('',#848,3.96875);
#850=CARTESIAN_POINT('',(-3.96875,34.9438839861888,0.));
#851=VERTEX_POINT('',#850);
#852=EDGE_CURVE('P1_E788',#851,#851,#849,.T.);
#853=ORIENTED_EDGE('',*,*,#852,.F.);
#854=EDGE_LOOP('',(#853));
#855=FACE_BOUND('',#854,.T.);
#856=ORIENTED_EDGE('',*,*,#832,.T.);
#857=EDGE_LOOP('',(#856));
#858=FACE_BOUND('',#857,.T.);
#859=ADVANCED_FACE('P1_F513',(#855,#858),#844,.T.);
#860=CARTESIAN_POINT('',(0.,55.5498,0.));
#861=DIRECTION('',(0.,1.,0.));
#862=DIRECTION('',(-1.,0.,0.));
#863=AXIS2_PLACEMENT_3D('',#860,#861,#862);
#864=CYLINDRICAL_SURFACE('',#863,3.96875);
#865=CARTESIAN_POINT('',(0.,39.0398,0.));
#866=DIRECTION('',(0.,1.,0.));
#867=DIRECTION('',(-1.,0.,0.));
#868=AXIS2_PLACEMENT_3D('',#865,#866,#867);
#869=CIRCLE('',#868,3.96875);
#870=CARTESIAN_POINT('',(-3.96875,39.0398,0.));
#871=VERTEX_POINT('',#870);
#872=EDGE_CURVE('P1_E791',#871,#871,#869,.T.);
#873=ORIENTED_EDGE('',*,*,#872,.F.);
#874=EDGE_LOOP('',(#873));
#875=FACE_BOUND('',#874,.T.);
#876=ORIENTED_EDGE('',*,*,#852,.T.);
#877=EDGE_LOOP('',(#876));
#878=FACE_BOUND('',#877,.T.);
#879=ADVANCED_FACE('P1_F522',(#875,#878),#864,.T.);
#880=CARTESIAN_POINT('',(0.,55.5498,0.));
#881=DIRECTION('',(0.,1.,0.));
#882=DIRECTION('',(-1.,0.,0.));
#883=AXIS2_PLACEMENT_3D('',#880,#881,#882);
#884=CYLINDRICAL_SURFACE('',#883,3.96875);
#885=CARTESIAN_POINT('',(0.,52.1051526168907,0.));
#886=DIRECTION('',(0.,1.,0.));
#887=DIRECTION('',(-1.,0.,0.));
#888=AXIS2_PLACEMENT_3D('',#885,#886,#887);
#889=CIRCLE('',#888,3.96875);
#890=CARTESIAN_POINT('',(-3.96875,52.1051526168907,0.));
#891=VERTEX_POINT('',#890);
#892=EDGE_CURVE('P1_E343',#891,#891,#889,.T.);
#893=ORIENTED_EDGE('',*,*,#892,.T.);
#894=EDGE_LOOP('',(#893));
#895=FACE_BOUND('',#894,.T.);
#896=CARTESIAN_POINT('',(0.,55.5498,0.));
#897=DIRECTION('',(0.,1.,0.));
#898=DIRECTION('',(0.,0.,1.));
#899=AXIS2_PLACEMENT_3D('',#896,#897,#898);
#900=CIRCLE('',#899,3.96875);
#901=CARTESIAN_POINT('',(0.,55.5498,3.96875));
#902=VERTEX_POINT('',#901);
#903=EDGE_CURVE('P1_E838',#902,#902,#900,.T.);
#904=ORIENTED_EDGE('',*,*,#903,.F.);
#905=EDGE_LOOP('',(#904));
#906=FACE_BOUND('',#905,.T.);
#907=ADVANCED_FACE('P1_F531',(#895,#906),#884,.T.);
#908=CARTESIAN_POINT('',(0.,48.895,0.));
#909=DIRECTION('',(0.,-1.,0.));
#910=DIRECTION('',(1.,0.,0.));
#911=AXIS2_PLACEMENT_3D('',#908,#909,#910);
#912=CONICAL_SURFACE('',#911,5.13715,0.349065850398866);
#913=ORIENTED_EDGE('',*,*,#892,.F.);
#914=EDGE_LOOP('',(#913));
#915=FACE_BOUND('',#914,.T.);
#916=CARTESIAN_POINT('',(0.,48.895,0.));
#917=DIRECTION('',(0.,1.,0.));
#918=DIRECTION('',(-1.,0.,0.));
#919=AXIS2_PLACEMENT_3D('',#916,#917,#918);
#920=CIRCLE('',#919,5.13715);
#921=CARTESIAN_POINT('',(-5.13715,48.895,0.));
#922=VERTEX_POINT('',#921);
#923=EDGE_CURVE('P1_E809',#922,#922,#920,.T.);
#924=ORIENTED_EDGE('',*,*,#923,.T.);
#925=EDGE_LOOP('',(#924));
#926=FACE_BOUND('',#925,.T.);
#927=ADVANCED_FACE('P1_F540',(#915,#926),#912,.T.);
#928=CARTESIAN_POINT('',(0.,55.5498,0.));
#929=DIRECTION('',(0.,1.,0.));
#930=DIRECTION('',(-1.,0.,0.));
#931=AXIS2_PLACEMENT_3D('',#928,#929,#930);
#932=CYLINDRICAL_SURFACE('',#931,5.13715);
#933=ORIENTED_EDGE('',*,*,#923,.F.);
#934=EDGE_LOOP('',(#933));
#935=FACE_BOUND('',#934,.T.);
#936=CARTESIAN_POINT('',(0.,47.625,0.));
#937=DIRECTION('',(0.,1.,0.));
#938=DIRECTION('',(-1.,0.,0.));
#939=AXIS2_PLACEMENT_3D('',#936,#937,#938);
#940=CIRCLE('',#939,5.13715);
#941=CARTESIAN_POINT('',(-5.13715,47.625,0.));
#942=VERTEX_POINT('',#941);
#943=EDGE_CURVE('P1_E806',#942,#942,#940,.T.);
#944=ORIENTED_EDGE('',*,*,#943,.T.);
#945=EDGE_LOOP('',(#944));
#946=FACE_BOUND('',#945,.T.);
#947=ADVANCED_FACE('P1_F438',(#935,#946),#932,.T.);
#948=CARTESIAN_POINT('',(0.,47.625,5.9182));
#949=DIRECTION('',(0.,-1.,0.));
#950=DIRECTION('',(0.,0.,-1.));
#951=AXIS2_PLACEMENT_3D('',#948,#949,#950);
#952=PLANE('',#951);
#953=ORIENTED_EDGE('',*,*,#943,.F.);
#954=EDGE_LOOP('',(#953));
#955=FACE_BOUND('',#954,.T.);
#956=CARTESIAN_POINT('',(0.,47.625,0.));
#957=DIRECTION('',(0.,1.,0.));
#958=DIRECTION('',(-1.,0.,0.));
#959=AXIS2_PLACEMENT_3D('',#956,#957,#958);
#960=CIRCLE('',#959,3.96875);
#961=CARTESIAN_POINT('',(-3.96875,47.625,0.));
#962=VERTEX_POINT('',#961);
#963=EDGE_CURVE('P1_E803',#962,#962,#960,.T.);
#964=ORIENTED_EDGE('',*,*,#963,.T.);
#965=EDGE_LOOP('',(#964));
#966=FACE_BOUND('',#965,.T.);
#967=ADVANCED_FACE('P1_F434',(#955,#966),#952,.T.);
#968=CARTESIAN_POINT('',(0.,55.5498,0.));
#969=DIRECTION('',(0.,1.,0.));
#970=DIRECTION('',(-1.,0.,0.));
#971=AXIS2_PLACEMENT_3D('',#968,#969,#970);
#972=CYLINDRICAL_SURFACE('',#971,3.96875);
#973=ORIENTED_EDGE('',*,*,#963,.F.);
#974=EDGE_LOOP('',(#973));
#975=FACE_BOUND('',#974,.T.);
#976=CARTESIAN_POINT('',(0.,43.5290839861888,0.));
#977=DIRECTION('',(0.,1.,0.));
#978=DIRECTION('',(-1.,0.,0.));
#979=AXIS2_PLACEMENT_3D('',#976,#977,#978);
#980=CIRCLE('',#979,3.96875);
#981=CARTESIAN_POINT('',(-3.96875,43.5290839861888,0.));
#982=VERTEX_POINT('',#981);
#983=EDGE_CURVE('P1_E800',#982,#982,#980,.T.);
#984=ORIENTED_EDGE('',*,*,#983,.T.);
#985=EDGE_LOOP('',(#984));
#986=FACE_BOUND('',#985,.T.);
#987=ADVANCED_FACE('P1_F437',(#975,#986),#972,.T.);
#988=CARTESIAN_POINT('',(0.,40.3098,0.));
#989=DIRECTION('',(0.,-1.,0.));
#990=DIRECTION('',(1.,0.,0.));
#991=AXIS2_PLACEMENT_3D('',#988,#989,#990);
#992=CONICAL_SURFACE('',#991,5.13715,0.348153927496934);
#993=ORIENTED_EDGE('',*,*,#983,.F.);
#994=EDGE_LOOP('',(#993));
#995=FACE_BOUND('',#994,.T.);
#996=CARTESIAN_POINT('',(0.,40.3098,0.));
#997=DIRECTION('',(0.,1.,0.));
#998=DIRECTION('',(-1.,0.,0.));
#999=AXIS2_PLACEMENT_3D('',#996,#997,#998);
#1000=CIRCLE('',#999,5.13715);
#1001=CARTESIAN_POINT('',(-5.13715,40.3098,0.));
#1002=VERTEX_POINT('',#1001);
#1003=EDGE_CURVE('P1_E797',#1002,#1002,#1000,.T.);
#1004=ORIENTED_EDGE('',*,*,#1003,.T.);
#1005=EDGE_LOOP('',(#1004));
#1006=FACE_BOUND('',#1005,.T.);
#1007=ADVANCED_FACE('P1_F570',(#995,#1006),#992,.T.);
#1008=CARTESIAN_POINT('',(0.,55.5498,0.));
#1009=DIRECTION('',(0.,1.,0.));
#1010=DIRECTION('',(-1.,0.,0.));
#1011=AXIS2_PLACEMENT_3D('',#1008,#1009,#1010);
#1012=CYLINDRICAL_SURFACE('',#1011,5.13715);
#1013=ORIENTED_EDGE('',*,*,#1003,.F.);
#1014=EDGE_LOOP('',(#1013));
#1015=FACE_BOUND('',#1014,.T.);
#1016=CARTESIAN_POINT('',(0.,39.0398,0.));
#1017=DIRECTION('',(0.,1.,0.));
#1018=DIRECTION('',(-1.,0.,0.));
#1019=AXIS2_PLACEMENT_3D('',#1016,#1017,#1018);
#1020=CIRCLE('',#1019,5.13715);
#1021=CARTESIAN_POINT('',(-5.13715,39.0398,0.));
#1022=VERTEX_POINT('',#1021);
#1023=EDGE_CURVE('P1_E794',#1022,#1022,#1020,.T.);
#1024=ORIENTED_EDGE('',*,*,#1023,.T.);
#1025=EDGE_LOOP('',(#1024));
#1026=FACE_BOUND('',#1025,.T.);
#1027=ADVANCED_FACE('P1_F451',(#1015,#1026),#1012,.T.);
#1028=CARTESIAN_POINT('',(0.,39.0398,5.969));
#1029=DIRECTION('',(0.,-1.,0.));
#1030=DIRECTION('',(0.,0.,-1.));
#1031=AXIS2_PLACEMENT_3D('',#1028,#1029,#1030);
#1032=PLANE('',#1031);
#1033=ORIENTED_EDGE('',*,*,#1023,.F.);
#1034=EDGE_LOOP('',(#1033));
#1035=FACE_BOUND('',#1034,.T.);
#1036=ORIENTED_EDGE('',*,*,#872,.T.);
#1037=EDGE_LOOP('',(#1036));
#1038=FACE_BOUND('',#1037,.T.);
#1039=ADVANCED_FACE('P1_F447',(#1035,#1038),#1032,.T.);
#1040=CARTESIAN_POINT('',(0.,26.9748,0.));
#1041=DIRECTION('',(0.,1.,0.));
#1042=DIRECTION('',(0.,0.,1.));
#1043=AXIS2_PLACEMENT_3D('',#1040,#1041,#1042);
#1044=PLANE('',#1043);
#1045=CARTESIAN_POINT('',(0.,26.9748,0.));
#1046=DIRECTION('',(0.,1.,0.));
#1047=DIRECTION('',(0.,0.,1.));
#1048=AXIS2_PLACEMENT_3D('',#1045,#1046,#1047);
#1049=CIRCLE('',#1048,2.921);
#1050=CARTESIAN_POINT('',(0.,26.9748,2.921));
#1051=VERTEX_POINT('',#1050);
#1052=EDGE_CURVE('P1_E779',#1051,#1051,#1049,.T.);
#1053=ORIENTED_EDGE('',*,*,#1052,.T.);
#1054=EDGE_LOOP('',(#1053));
#1055=FACE_BOUND('',#1054,.T.);
#1056=ORIENTED_EDGE('',*,*,#736,.F.);
#1057=EDGE_LOOP('',(#1056));
#1058=FACE_BOUND('',#1057,.T.);
#1059=ADVANCED_FACE('P1_F450',(#1055,#1058),#1044,.F.);
#1060=CARTESIAN_POINT('',(0.,55.5498,0.));
#1061=DIRECTION('',(0.,1.,0.));
#1062=DIRECTION('',(0.,0.,1.));
#1063=AXIS2_PLACEMENT_3D('',#1060,#1061,#1062);
#1064=PLANE('',#1063);
#1065=CARTESIAN_POINT('',(0.,55.5498,0.));
#1066=DIRECTION('',(0.,1.,0.));
#1067=DIRECTION('',(0.,0.,1.));
#1068=AXIS2_PLACEMENT_3D('',#1065,#1066,#1067);
#1069=CIRCLE('',#1068,2.921);
#1070=CARTESIAN_POINT('',(0.,55.5498,2.921));
#1071=VERTEX_POINT('',#1070);
#1072=EDGE_CURVE('P1_E773',#1071,#1071,#1069,.T.);
#1073=ORIENTED_EDGE('',*,*,#1072,.F.);
#1074=EDGE_LOOP('',(#1073));
#1075=FACE_BOUND('',#1074,.T.);
#1076=ORIENTED_EDGE('',*,*,#903,.T.);
#1077=EDGE_LOOP('',(#1076));
#1078=FACE_BOUND('',#1077,.T.);
#1079=ADVANCED_FACE('P1_F600',(#1075,#1078),#1064,.T.);
#1080=CARTESIAN_POINT('',(0.,55.5498,0.));
#1081=DIRECTION('',(0.,-1.,0.));
#1082=DIRECTION('',(0.,0.,-1.));
#1083=AXIS2_PLACEMENT_3D('',#1080,#1081,#1082);
#1084=CYLINDRICAL_SURFACE('',#1083,2.921);
#1085=ORIENTED_EDGE('',*,*,#1072,.T.);
#1086=EDGE_LOOP('',(#1085));
#1087=FACE_BOUND('',#1086,.T.);
#1088=ORIENTED_EDGE('',*,*,#1052,.F.);
#1089=EDGE_LOOP('',(#1088));
#1090=FACE_BOUND('',#1089,.T.);
#1091=ADVANCED_FACE('P1_F609',(#1087,#1090),#1084,.F.);
#1092=CLOSED_SHELL('',(#217,#238,#273,#325,#373,#394,#430,#444,#478,#513,#564,#599,#634,#669,
#704,#723,#765,#779,#807,#819,#839,#859,#879,#907,#927,#947,#967,#987,#1007,#1027,#1039,#1059,
#1079,#1091));
#1093=MANIFOLD_SOLID_BREP('P1_B1',#1092);
#1094=CARTESIAN_POINT('',(0.,25.2095,0.));
#1095=DIRECTION('',(0.,-1.,0.));
#1096=DIRECTION('',(0.,0.,-1.));
#1097=AXIS2_PLACEMENT_3D('',#1094,#1095,#1096);
#1098=CONICAL_SURFACE('',#1097,9.3345,0.785398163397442);
#1099=CARTESIAN_POINT('',(0.,25.4,0.));
#1100=DIRECTION('',(0.,-1.,0.));
#1101=DIRECTION('',(0.,0.,-1.));
#1102=AXIS2_PLACEMENT_3D('',#1099,#1100,#1101);
#1103=CIRCLE('',#1102,9.144);
#1104=CARTESIAN_POINT('',(0.,25.4,9.144));
#1105=VERTEX_POINT('',#1104);
#1106=EDGE_CURVE('P2_E11',#1105,#1105,#1103,.T.);
#1107=ORIENTED_EDGE('',*,*,#1106,.T.);
#1108=DIRECTION('',(0.,-0.707106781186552,0.707106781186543));
#1109=VECTOR('',#1108,1.);
#1110=CARTESIAN_POINT('',(0.,25.2095,9.3345));
#1111=LINE('',#1110,#1109);
#1112=CARTESIAN_POINT('',(0.,25.019,9.525));
#1113=VERTEX_POINT('',#1112);
#1114=EDGE_CURVE('P2_E27',#1105,#1113,#1111,.T.);
#1115=ORIENTED_EDGE('',*,*,#1114,.T.);
#1116=CARTESIAN_POINT('',(0.,25.019,0.));
#1117=DIRECTION('',(0.,1.,0.));
#1118=DIRECTION('',(0.,0.,-1.));
#1119=AXIS2_PLACEMENT_3D('',#1116,#1117,#1118);
#1120=CIRCLE('',#1119,9.525);
#1121=CARTESIAN_POINT('',(0.,25.019,-9.525));
#1122=VERTEX_POINT('',#1121);
#1123=EDGE_CURVE('P2_E168',#1113,#1122,#1120,.T.);
#1124=ORIENTED_EDGE('',*,*,#1123,.T.);
#1125=CARTESIAN_POINT('',(0.,25.019,0.));
#1126=DIRECTION('',(0.,1.,0.));
#1127=DIRECTION('',(0.,0.,-1.));
#1128=AXIS2_PLACEMENT_3D('',#1125,#1126,#1127);
#1129=CIRCLE('',#1128,9.525);
#1130=EDGE_CURVE('P2_E272',#1122,#1113,#1129,.T.);
#1131=ORIENTED_EDGE('',*,*,#1130,.T.);
#1132=ORIENTED_EDGE('',*,*,#1114,.F.);
#1133=EDGE_LOOP('',(#1107,#1115,#1124,#1131,#1132));
#1134=FACE_BOUND('',#1133,.T.);
#1135=ADVANCED_FACE('P2_F16',(#1134),#1098,.T.);
#1136=CARTESIAN_POINT('',(0.,20.828,0.));
#1137=DIRECTION('',(0.,1.,0.));
#1138=DIRECTION('',(0.,0.,1.));
#1139=AXIS2_PLACEMENT_3D('',#1136,#1137,#1138);
#1140=CYLINDRICAL_SURFACE('',#1139,9.525);
#1141=ORIENTED_EDGE('',*,*,#1123,.F.);
#1142=ORIENTED_EDGE('',*,*,#1130,.F.);
#1143=DIRECTION('',(0.,-1.,0.));
#1144=VECTOR('',#1143,1.);
#1145=CARTESIAN_POINT('',(0.,20.828,-9.525));
#1146=LINE('',#1145,#1144);
#1147=CARTESIAN_POINT('',(0.,16.764,-9.525));
#1148=VERTEX_POINT('',#1147);
#1149=EDGE_CURVE('P2_E202',#1122,#1148,#1146,.T.);
#1150=ORIENTED_EDGE('',*,*,#1149,.T.);
#1151=CARTESIAN_POINT('',(0.,16.764,0.));
#1152=DIRECTION('',(0.,-1.,0.));
#1153=DIRECTION('',(0.,0.,-1.));
#1154=AXIS2_PLACEMENT_3D('',#1151,#1152,#1153);
#1155=CIRCLE('',#1154,9.525);
#1156=CARTESIAN_POINT('',(0.,16.764,9.525));
#1157=VERTEX_POINT('',#1156);
#1158=EDGE_CURVE('P2_E146',#1157,#1148,#1155,.T.);
#1159=ORIENTED_EDGE('',*,*,#1158,.F.);
#1160=CARTESIAN_POINT('',(0.,16.764,0.));
#1161=DIRECTION('',(0.,-1.,0.));
#1162=DIRECTION('',(0.,0.,-1.));
#1163=AXIS2_PLACEMENT_3D('',#1160,#1161,#1162);
#1164=CIRCLE('',#1163,9.525);
#1165=EDGE_CURVE('P2_E207',#1148,#1157,#1164,.T.);
#1166=ORIENTED_EDGE('',*,*,#1165,.F.);
#1167=ORIENTED_EDGE('',*,*,#1149,.F.);
#1168=EDGE_LOOP('',(#1141,#1142,#1150,#1159,#1166,#1167));
#1169=FACE_BOUND('',#1168,.T.);
#1170=ADVANCED_FACE('P2_F367',(#1169),#1140,.T.);
#1171=CARTESIAN_POINT('',(0.,25.4,7.4549));
#1172=DIRECTION('',(0.,1.,0.));
#1173=DIRECTION('',(1.,0.,0.));
#1174=AXIS2_PLACEMENT_3D('',#1171,#1172,#1173);
#1175=PLANE('',#1174);
#1176=ORIENTED_EDGE('',*,*,#1106,.F.);
#1177=EDGE_LOOP('',(#1176));
#1178=FACE_BOUND('',#1177,.T.);
#1179=CARTESIAN_POINT('',(0.,25.4,0.));
#1180=DIRECTION('',(0.,1.,0.));
#1181=DIRECTION('',(0.,0.,-1.));
#1182=AXIS2_PLACEMENT_3D('',#1179,#1180,#1181);
#1183=CIRCLE('',#1182,7.5819);
#1184=CARTESIAN_POINT('',(0.,25.4,-7.5819));
#1185=VERTEX_POINT('',#1184);
#1186=EDGE_CURVE('P2_E237',#1185,#1185,#1183,.T.);
#1187=ORIENTED_EDGE('',*,*,#1186,.F.);
#1188=EDGE_LOOP('',(#1187));
#1189=FACE_BOUND('',#1188,.T.);
#1190=ADVANCED_FACE('P2_F373',(#1178,#1189),#1175,.T.);
#1191=CARTESIAN_POINT('',(0.,6.096,0.));
#1192=DIRECTION('',(0.,1.,0.));
#1193=DIRECTION('',(0.,0.,1.));
#1194=AXIS2_PLACEMENT_3D('',#1191,#1192,#1193);
#1195=TOROIDAL_SURFACE('',#1194,6.6802,0.254);
#1196=CARTESIAN_POINT('',(0.,6.096,0.));
#1197=DIRECTION('',(0.,-1.,0.));
#1198=DIRECTION('',(0.,0.,-1.));
#1199=AXIS2_PLACEMENT_3D('',#1196,#1197,#1198);
#1200=CIRCLE('',#1199,6.4262);
#1201=CARTESIAN_POINT('',(0.,6.096,6.4262));
#1202=VERTEX_POINT('',#1201);
#1203=CARTESIAN_POINT('',(0.,6.096,-6.4262));
#1204=VERTEX_POINT('',#1203);
#1205=EDGE_CURVE('P2_E199',#1202,#1204,#1200,.T.);
#1206=ORIENTED_EDGE('',*,*,#1205,.T.);
#1207=CARTESIAN_POINT('',(0.,6.096,-6.6802));
#1208=DIRECTION('',(-1.,0.,0.));
#1209=DIRECTION('',(0.,0.,-1.));
#1210=AXIS2_PLACEMENT_3D('',#1207,#1208,#1209);
#1211=CIRCLE('',#1210,0.254);
#1212=CARTESIAN_POINT('',(0.,6.35,-6.6802));
#1213=VERTEX_POINT('',#1212);
#1214=EDGE_CURVE('P2_E188',#1204,#1213,#1211,.T.);
#1215=ORIENTED_EDGE('',*,*,#1214,.T.);
#1216=CARTESIAN_POINT('',(0.,6.35,0.));
#1217=DIRECTION('',(0.,1.,0.));
#1218=DIRECTION('',(0.,0.,-1.));
#1219=AXIS2_PLACEMENT_3D('',#1216,#1217,#1218);
#1220=CIRCLE('',#1219,6.6802);
#1221=CARTESIAN_POINT('',(0.,6.35,6.6802));
#1222=VERTEX_POINT('',#1221);
#1223=EDGE_CURVE('P2_E184',#1213,#1222,#1220,.T.);
#1224=ORIENTED_EDGE('',*,*,#1223,.T.);
#1225=CARTESIAN_POINT('',(0.,6.35,0.));
#1226=DIRECTION('',(0.,1.,0.));
#1227=DIRECTION('',(0.,0.,-1.));
#1228=AXIS2_PLACEMENT_3D('',#1225,#1226,#1227);
#1229=CIRCLE('',#1228,6.6802);
#1230=EDGE_CURVE('P2_E189',#1222,#1213,#1229,.T.);
#1231=ORIENTED_EDGE('',*,*,#1230,.T.);
#1232=ORIENTED_EDGE('',*,*,#1214,.F.);
#1233=CARTESIAN_POINT('',(0.,6.096,0.));
#1234=DIRECTION('',(0.,-1.,0.));
#1235=DIRECTION('',(0.,0.,-1.));
#1236=AXIS2_PLACEMENT_3D('',#1233,#1234,#1235);
#1237=CIRCLE('',#1236,6.4262);
#1238=EDGE_CURVE('P2_E193',#1204,#1202,#1237,.T.);
#1239=ORIENTED_EDGE('',*,*,#1238,.T.);
#1240=EDGE_LOOP('',(#1206,#1215,#1224,#1231,#1232,#1239));
#1241=FACE_BOUND('',#1240,.T.);
#1242=ADVANCED_FACE('P2_F302',(#1241),#1195,.T.);
#1243=CARTESIAN_POINT('',(0.,6.35,6.4262));
#1244=DIRECTION('',(0.,1.,0.));
#1245=DIRECTION('',(1.,0.,0.));
#1246=AXIS2_PLACEMENT_3D('',#1243,#1244,#1245);
#1247=PLANE('',#1246);
#1248=CARTESIAN_POINT('',(0.,6.35,0.));
#1249=DIRECTION('',(0.,-1.,0.));
#1250=DIRECTION('',(0.,0.,-1.));
#1251=AXIS2_PLACEMENT_3D('',#1248,#1249,#1250);
#1252=CIRCLE('',#1251,7.2009);
#1253=CARTESIAN_POINT('',(0.,6.35,7.2009));
#1254=VERTEX_POINT('',#1253);
#1255=CARTESIAN_POINT('',(0.,6.35,-7.2009));
#1256=VERTEX_POINT('',#1255);
#1257=EDGE_CURVE('P2_E138',#1254,#1256,#1252,.T.);
#1258=ORIENTED_EDGE('',*,*,#1257,.F.);
#1259=CARTESIAN_POINT('',(0.,6.35,0.));
#1260=DIRECTION('',(0.,-1.,0.));
#1261=DIRECTION('',(0.,0.,-1.));
#1262=AXIS2_PLACEMENT_3D('',#1259,#1260,#1261);
#1263=CIRCLE('',#1262,7.2009);
#1264=EDGE_CURVE('P2_E143',#1256,#1254,#1263,.T.);
#1265=ORIENTED_EDGE('',*,*,#1264,.F.);
#1266=EDGE_LOOP('',(#1258,#1265));
#1267=FACE_BOUND('',#1266,.T.);
#1268=ORIENTED_EDGE('',*,*,#1230,.F.);
#1269=ORIENTED_EDGE('',*,*,#1223,.F.);
#1270=EDGE_LOOP('',(#1268,#1269));
#1271=FACE_BOUND('',#1270,.T.);
#1272=ADVANCED_FACE('P2_F298',(#1267,#1271),#1247,.T.);
#1273=CARTESIAN_POINT('',(0.,4.1402,0.));
#1274=DIRECTION('',(0.,1.,0.));
#1275=DIRECTION('',(0.,0.,1.));
#1276=AXIS2_PLACEMENT_3D('',#1273,#1274,#1275);
#1277=CYLINDRICAL_SURFACE('',#1276,6.4262);
#1278=ORIENTED_EDGE('',*,*,#1205,.F.);
#1279=ORIENTED_EDGE('',*,*,#1238,.F.);
#1280=DIRECTION('',(0.,-1.,0.));
#1281=VECTOR('',#1280,1.);
#1282=CARTESIAN_POINT('',(0.,4.1402,-6.4262));
#1283=LINE('',#1282,#1281);
#1284=CARTESIAN_POINT('',(0.,1.9304,-6.4262));
#1285=VERTEX_POINT('',#1284);
#1286=EDGE_CURVE('P2_E133',#1204,#1285,#1283,.T.);
#1287=ORIENTED_EDGE('',*,*,#1286,.T.);
#1288=CARTESIAN_POINT('',(0.,1.9304,0.));
#1289=DIRECTION('',(0.,1.,0.));
#1290=DIRECTION('',(1.,0.,0.));
#1291=AXIS2_PLACEMENT_3D('',#1288,#1289,#1290);
#1292=CIRCLE('',#1291,6.4262);
#1293=CARTESIAN_POINT('',(0.,1.9304,6.4262));
#1294=VERTEX_POINT('',#1293);
#1295=EDGE_CURVE('P2_E180',#1294,#1285,#1292,.T.);
#1296=ORIENTED_EDGE('',*,*,#1295,.F.);
#1297=CARTESIAN_POINT('',(0.,1.9304,0.));
#1298=DIRECTION('',(0.,1.,0.));
#1299=DIRECTION('',(1.,0.,0.));
#1300=AXIS2_PLACEMENT_3D('',#1297,#1298,#1299);
#1301=CIRCLE('',#1300,6.4262);
#1302=EDGE_CURVE('P2_E160',#1285,#1294,#1301,.T.);
#1303=ORIENTED_EDGE('',*,*,#1302,.F.);
#1304=ORIENTED_EDGE('',*,*,#1286,.F.);
#1305=EDGE_LOOP('',(#1278,#1279,#1287,#1296,#1303,#1304));
#1306=FACE_BOUND('',#1305,.T.);
#1307=ADVANCED_FACE('P2_F301',(#1306),#1277,.F.);
#1308=CARTESIAN_POINT('',(0.,6.604,0.));
#1309=DIRECTION('',(0.,1.,0.));
#1310=DIRECTION('',(0.,0.,1.));
#1311=AXIS2_PLACEMENT_3D('',#1308,#1309,#1310);
#1312=TOROIDAL_SURFACE('',#1311,7.2009,0.254);
#1313=CARTESIAN_POINT('',(0.,6.604,0.));
#1314=DIRECTION('',(0.,1.,0.));
#1315=DIRECTION('',(0.,0.,-1.));
#1316=AXIS2_PLACEMENT_3D('',#1313,#1314,#1315);
#1317=CIRCLE('',#1316,7.4549);
#1318=CARTESIAN_POINT('',(0.,6.604,7.4549));
#1319=VERTEX_POINT('',#1318);
#1320=CARTESIAN_POINT('',(0.,6.604,-7.4549));
#1321=VERTEX_POINT('',#1320);
#1322=EDGE_CURVE('P2_E123',#1319,#1321,#1317,.T.);
#1323=ORIENTED_EDGE('',*,*,#1322,.T.);
#1324=CARTESIAN_POINT('',(0.,6.604,-7.2009));
#1325=DIRECTION('',(-1.,0.,0.));
#1326=DIRECTION('',(0.,0.,-1.));
#1327=AXIS2_PLACEMENT_3D('',#1324,#1325,#1326);
#1328=CIRCLE('',#1327,0.254);
#1329=EDGE_CURVE('P2_E134',#1321,#1256,#1328,.T.);
#1330=ORIENTED_EDGE('',*,*,#1329,.T.);
#1331=ORIENTED_EDGE('',*,*,#1264,.T.);
#1332=ORIENTED_EDGE('',*,*,#1257,.T.);
#1333=ORIENTED_EDGE('',*,*,#1329,.F.);
#1334=CARTESIAN_POINT('',(0.,6.604,0.));
#1335=DIRECTION('',(0.,1.,0.));
#1336=DIRECTION('',(0.,0.,-1.));
#1337=AXIS2_PLACEMENT_3D('',#1334,#1335,#1336);
#1338=CIRCLE('',#1337,7.4549);
#1339=EDGE_CURVE('P2_E127',#1321,#1319,#1338,.T.);
#1340=ORIENTED_EDGE('',*,*,#1339,.T.);
#1341=EDGE_LOOP('',(#1323,#1330,#1331,#1332,#1333,#1340));
#1342=FACE_BOUND('',#1341,.T.);
#1343=ADVANCED_FACE('P2_F136',(#1342),#1312,.F.);
#1344=CARTESIAN_POINT('',(0.,15.875,0.));
#1345=DIRECTION('',(0.,1.,0.));
#1346=DIRECTION('',(0.,0.,1.));
#1347=AXIS2_PLACEMENT_3D('',#1344,#1345,#1346);
#1348=CYLINDRICAL_SURFACE('',#1347,7.4549);
#1349=CARTESIAN_POINT('',(0.,25.273,0.));
#1350=DIRECTION('',(0.,-1.,0.));
#1351=DIRECTION('',(0.,0.,-1.));
#1352=AXIS2_PLACEMENT_3D('',#1349,#1350,#1351);
#1353=CIRCLE('',#1352,7.4549);
#1354=CARTESIAN_POINT('',(0.,25.273,7.4549));
#1355=VERTEX_POINT('',#1354);
#1356=CARTESIAN_POINT('',(0.,25.273,-7.4549));
#1357=VERTEX_POINT('',#1356);
#1358=EDGE_CURVE('P2_E169',#1355,#1357,#1353,.T.);
#1359=ORIENTED_EDGE('',*,*,#1358,.F.);
#1360=CARTESIAN_POINT('',(0.,25.273,0.));
#1361=DIRECTION('',(0.,-1.,0.));
#1362=DIRECTION('',(0.,0.,-1.));
#1363=AXIS2_PLACEMENT_3D('',#1360,#1361,#1362);
#1364=CIRCLE('',#1363,7.4549);
#1365=EDGE_CURVE('P2_E233',#1357,#1355,#1364,.T.);
#1366=ORIENTED_EDGE('',*,*,#1365,.F.);
#1367=DIRECTION('',(0.,-1.,0.));
#1368=VECTOR('',#1367,1.);
#1369=CARTESIAN_POINT('',(0.,15.875,-7.4549));
#1370=LINE('',#1369,#1368);
#1371=EDGE_CURVE('P2_E129',#1357,#1321,#1370,.T.);
#1372=ORIENTED_EDGE('',*,*,#1371,.T.);
#1373=ORIENTED_EDGE('',*,*,#1322,.F.);
#1374=ORIENTED_EDGE('',*,*,#1339,.F.);
#1375=ORIENTED_EDGE('',*,*,#1371,.F.);
#1376=EDGE_LOOP('',(#1359,#1366,#1372,#1373,#1374,#1375));
#1377=FACE_BOUND('',#1376,.T.);
#1378=ADVANCED_FACE('P2_F125',(#1377),#1348,.F.);
#1379=CARTESIAN_POINT('',(0.,16.51,0.));
#1380=DIRECTION('',(0.,1.,0.));
#1381=DIRECTION('',(0.,0.,-1.));
#1382=AXIS2_PLACEMENT_3D('',#1379,#1380,#1381);
#1383=CONICAL_SURFACE('',#1382,9.271,0.785398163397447);
#1384=ORIENTED_EDGE('',*,*,#1158,.T.);
#1385=ORIENTED_EDGE('',*,*,#1165,.T.);
#1386=DIRECTION('',(0.,-0.707106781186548,-0.707106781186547));
#1387=VECTOR('',#1386,1.);
#1388=CARTESIAN_POINT('',(0.,16.51,9.271));
#1389=LINE('',#1388,#1387);
#1390=CARTESIAN_POINT('',(0.,16.256,9.017));
#1391=VERTEX_POINT('',#1390);
#1392=EDGE_CURVE('P2_E152',#1157,#1391,#1389,.T.);
#1393=ORIENTED_EDGE('',*,*,#1392,.T.);
#1394=CARTESIAN_POINT('',(0.,16.256,0.));
#1395=DIRECTION('',(0.,1.,0.));
#1396=DIRECTION('',(0.,0.,-1.));
#1397=AXIS2_PLACEMENT_3D('',#1394,#1395,#1396);
#1398=CIRCLE('',#1397,9.017);
#1399=EDGE_CURVE('P2_E149',#1391,#1391,#1398,.T.);
#1400=ORIENTED_EDGE('',*,*,#1399,.T.);
#1401=ORIENTED_EDGE('',*,*,#1392,.F.);
#1402=EDGE_LOOP('',(#1384,#1385,#1393,#1400,#1401));
#1403=FACE_BOUND('',#1402,.T.);
#1404=ADVANCED_FACE('P2_F354',(#1403),#1383,.T.);
#1405=CARTESIAN_POINT('',(0.,16.256,9.525));
#1406=DIRECTION('',(0.,-1.,0.));
#1407=DIRECTION('',(0.,0.,-1.));
#1408=AXIS2_PLACEMENT_3D('',#1405,#1406,#1407);
#1409=PLANE('',#1408);
#1410=ORIENTED_EDGE('',*,*,#1399,.F.);
#1411=EDGE_LOOP('',(#1410));
#1412=FACE_BOUND('',#1411,.T.);
#1413=CARTESIAN_POINT('',(0.,16.256,0.));
#1414=DIRECTION('',(0.,1.,0.));
#1415=DIRECTION('',(1.,0.,0.));
#1416=AXIS2_PLACEMENT_3D('',#1413,#1414,#1415);
#1417=CIRCLE('',#1416,8.4328);
#1418=CARTESIAN_POINT('',(0.,16.256,8.4328));
#1419=VERTEX_POINT('',#1418);
#1420=CARTESIAN_POINT('',(0.,16.256,-8.4328));
#1421=VERTEX_POINT('',#1420);
#1422=EDGE_CURVE('P2_E153',#1419,#1421,#1417,.T.);
#1423=ORIENTED_EDGE('',*,*,#1422,.T.);
#1424=CARTESIAN_POINT('',(0.,16.256,0.));
#1425=DIRECTION('',(0.,1.,0.));
#1426=DIRECTION('',(1.,0.,0.));
#1427=AXIS2_PLACEMENT_3D('',#1424,#1425,#1426);
#1428=CIRCLE('',#1427,8.4328);
#1429=EDGE_CURVE('P2_E217',#1421,#1419,#1428,.T.);
#1430=ORIENTED_EDGE('',*,*,#1429,.T.);
#1431=EDGE_LOOP('',(#1423,#1430));
#1432=FACE_BOUND('',#1431,.T.);
#1433=ADVANCED_FACE('P2_F352',(#1412,#1432),#1409,.T.);
#1434=CARTESIAN_POINT('',(0.,0.127,0.));
#1435=DIRECTION('',(0.,1.,0.));
#1436=DIRECTION('',(0.,0.,1.));
#1437=AXIS2_PLACEMENT_3D('',#1434,#1435,#1436);
#1438=TOROIDAL_SURFACE('',#1437,8.3058,0.127);
#1439=CARTESIAN_POINT('',(0.,0.127,0.));
#1440=DIRECTION('',(0.,-1.,0.));
#1441=DIRECTION('',(0.,0.,-1.));
#1442=AXIS2_PLACEMENT_3D('',#1439,#1440,#1441);
#1443=CIRCLE('',#1442,8.4328);
#1444=CARTESIAN_POINT('',(0.,0.127,8.4328));
#1445=VERTEX_POINT('',#1444);
#1446=CARTESIAN_POINT('',(0.,0.127,-8.4328));
#1447=VERTEX_POINT('',#1446);
#1448=EDGE_CURVE('P2_E221',#1445,#1447,#1443,.T.);
#1449=ORIENTED_EDGE('',*,*,#1448,.T.);
#1450=CARTESIAN_POINT('',(0.,0.127,-8.3058));
#1451=DIRECTION('',(-1.,0.,0.));
#1452=DIRECTION('',(0.,0.,-1.));
#1453=AXIS2_PLACEMENT_3D('',#1450,#1451,#1452);
#1454=CIRCLE('',#1453,0.127);
#1455=CARTESIAN_POINT('',(0.,0.,-8.3058));
#1456=VERTEX_POINT('',#1455);
#1457=EDGE_CURVE('P2_E259',#1447,#1456,#1454,.T.);
#1458=ORIENTED_EDGE('',*,*,#1457,.T.);
#1459=CARTESIAN_POINT('',(0.,0.,0.));
#1460=DIRECTION('',(0.,1.,0.));
#1461=DIRECTION('',(0.,0.,-1.));
#1462=AXIS2_PLACEMENT_3D('',#1459,#1460,#1461);
#1463=CIRCLE('',#1462,8.3058);
#1464=CARTESIAN_POINT('',(0.,0.,8.3058));
#1465=VERTEX_POINT('',#1464);
#1466=EDGE_CURVE('P2_E20',#1456,#1465,#1463,.T.);
#1467=ORIENTED_EDGE('',*,*,#1466,.T.);
#1468=CARTESIAN_POINT('',(0.,0.,0.));
#1469=DIRECTION('',(0.,1.,0.));
#1470=DIRECTION('',(0.,0.,-1.));
#1471=AXIS2_PLACEMENT_3D('',#1468,#1469,#1470);
#1472=CIRCLE('',#1471,8.3058);
#1473=EDGE_CURVE('P2_E198',#1465,#1456,#1472,.T.);
#1474=ORIENTED_EDGE('',*,*,#1473,.T.);
#1475=ORIENTED_EDGE('',*,*,#1457,.F.);
#1476=CARTESIAN_POINT('',(0.,0.127,0.));
#1477=DIRECTION('',(0.,-1.,0.));
#1478=DIRECTION('',(0.,0.,-1.));
#1479=AXIS2_PLACEMENT_3D('',#1476,#1477,#1478);
#1480=CIRCLE('',#1479,8.4328);
#1481=EDGE_CURVE('P2_E194',#1447,#1445,#1480,.T.);
#1482=ORIENTED_EDGE('',*,*,#1481,.T.);
#1483=EDGE_LOOP('',(#1449,#1458,#1467,#1474,#1475,#1482));
#1484=FACE_BOUND('',#1483,.T.);
#1485=ADVANCED_FACE('P2_F18',(#1484),#1438,.T.);
#1486=CARTESIAN_POINT('',(0.,0.,8.4328));
#1487=DIRECTION('',(0.,-1.,0.));
#1488=DIRECTION('',(0.,0.,-1.));
#1489=AXIS2_PLACEMENT_3D('',#1486,#1487,#1488);
#1490=PLANE('',#1489);
#1491=ORIENTED_EDGE('',*,*,#1473,.F.);
#1492=ORIENTED_EDGE('',*,*,#1466,.F.);
#1493=EDGE_LOOP('',(#1491,#1492));
#1494=FACE_BOUND('',#1493,.T.);
#1495=CARTESIAN_POINT('',(0.,0.,0.));
#1496=DIRECTION('',(0.,-1.,0.));
#1497=DIRECTION('',(0.,0.,-1.));
#1498=AXIS2_PLACEMENT_3D('',#1495,#1496,#1497);
#1499=CIRCLE('',#1498,7.4422);
#1500=CARTESIAN_POINT('',(0.,0.,7.4422));
#1501=VERTEX_POINT('',#1500);
#1502=CARTESIAN_POINT('',(0.,0.,-7.4422));
#1503=VERTEX_POINT('',#1502);
#1504=EDGE_CURVE('P2_E212',#1501,#1503,#1499,.T.);
#1505=ORIENTED_EDGE('',*,*,#1504,.F.);
#1506=CARTESIAN_POINT('',(0.,0.,0.));
#1507=DIRECTION('',(0.,-1.,0.));
#1508=DIRECTION('',(0.,0.,-1.));
#1509=AXIS2_PLACEMENT_3D('',#1506,#1507,#1508);
#1510=CIRCLE('',#1509,7.4422);
#1511=EDGE_CURVE('P2_E175',#1503,#1501,#1510,.T.);
#1512=ORIENTED_EDGE('',*,*,#1511,.F.);
#1513=EDGE_LOOP('',(#1505,#1512));
#1514=FACE_BOUND('',#1513,.T.);
#1515=ADVANCED_FACE('P2_F347',(#1494,#1514),#1490,.T.);
#1516=CARTESIAN_POINT('',(0.,8.128,0.));
#1517=DIRECTION('',(0.,1.,0.));
#1518=DIRECTION('',(0.,0.,1.));
#1519=AXIS2_PLACEMENT_3D('',#1516,#1517,#1518);
#1520=CYLINDRICAL_SURFACE('',#1519,8.4328);
#1521=ORIENTED_EDGE('',*,*,#1422,.F.);
#1522=ORIENTED_EDGE('',*,*,#1429,.F.);
#1523=DIRECTION('',(0.,-1.,0.));
#1524=VECTOR('',#1523,1.);
#1525=CARTESIAN_POINT('',(0.,8.128,-8.4328));
#1526=LINE('',#1525,#1524);
#1527=EDGE_CURVE('P2_E173',#1421,#1447,#1526,.T.);
#1528=ORIENTED_EDGE('',*,*,#1527,.T.);
#1529=ORIENTED_EDGE('',*,*,#1448,.F.);
#1530=ORIENTED_EDGE('',*,*,#1481,.F.);
#1531=ORIENTED_EDGE('',*,*,#1527,.F.);
#1532=EDGE_LOOP('',(#1521,#1522,#1528,#1529,#1530,#1531));
#1533=FACE_BOUND('',#1532,.T.);
#1534=ADVANCED_FACE('P2_F350',(#1533),#1520,.T.);
#1535=CARTESIAN_POINT('',(0.,25.273,0.));
#1536=DIRECTION('',(0.,1.,0.));
#1537=DIRECTION('',(0.,0.,1.));
#1538=AXIS2_PLACEMENT_3D('',#1535,#1536,#1537);
#1539=TOROIDAL_SURFACE('',#1538,7.5819,0.127);
#1540=ORIENTED_EDGE('',*,*,#1358,.T.);
#1541=CARTESIAN_POINT('',(0.,25.273,-7.5819));
#1542=DIRECTION('',(-1.,0.,0.));
#1543=DIRECTION('',(0.,0.,-1.));
#1544=AXIS2_PLACEMENT_3D('',#1541,#1542,#1543);
#1545=CIRCLE('',#1544,0.127);
#1546=EDGE_CURVE('P2_E174',#1357,#1185,#1545,.T.);
#1547=ORIENTED_EDGE('',*,*,#1546,.T.);
#1548=ORIENTED_EDGE('',*,*,#1186,.T.);
#1549=ORIENTED_EDGE('',*,*,#1546,.F.);
#1550=ORIENTED_EDGE('',*,*,#1365,.T.);
#1551=EDGE_LOOP('',(#1540,#1547,#1548,#1549,#1550));
#1552=FACE_BOUND('',#1551,.T.);
#1553=ADVANCED_FACE('P2_F391',(#1552),#1539,.T.);
#1554=CARTESIAN_POINT('',(0.,0.127,0.));
#1555=DIRECTION('',(0.,1.,0.));
#1556=DIRECTION('',(0.,0.,1.));
#1557=AXIS2_PLACEMENT_3D('',#1554,#1555,#1556);
#1558=TOROIDAL_SURFACE('',#1557,7.4422,0.127);
#1559=ORIENTED_EDGE('',*,*,#1504,.T.);
#1560=CARTESIAN_POINT('',(0.,0.127,-7.4422));
#1561=DIRECTION('',(-1.,0.,0.));
#1562=DIRECTION('',(0.,0.,-1.));
#1563=AXIS2_PLACEMENT_3D('',#1560,#1561,#1562);
#1564=CIRCLE('',#1563,0.127);
#1565=CARTESIAN_POINT('',(0.,0.127,-7.3152));
#1566=VERTEX_POINT('',#1565);
#1567=EDGE_CURVE('P2_E208',#1503,#1566,#1564,.T.);
#1568=ORIENTED_EDGE('',*,*,#1567,.T.);
#1569=CARTESIAN_POINT('',(0.,0.127,0.));
#1570=DIRECTION('',(0.,1.,0.));
#1571=DIRECTION('',(0.,0.,-1.));
#1572=AXIS2_PLACEMENT_3D('',#1569,#1570,#1571);
#1573=CIRCLE('',#1572,7.3152);
#1574=CARTESIAN_POINT('',(0.,0.127,7.3152));
#1575=VERTEX_POINT('',#1574);
#1576=EDGE_CURVE('P2_E213',#1566,#1575,#1573,.T.);
#1577=ORIENTED_EDGE('',*,*,#1576,.T.);
#1578=CARTESIAN_POINT('',(0.,0.127,0.));
#1579=DIRECTION('',(0.,1.,0.));
#1580=DIRECTION('',(0.,0.,-1.));
#1581=AXIS2_PLACEMENT_3D('',#1578,#1579,#1580);
#1582=CIRCLE('',#1581,7.3152);
#1583=EDGE_CURVE('P2_E179',#1575,#1566,#1582,.T.);
#1584=ORIENTED_EDGE('',*,*,#1583,.T.);
#1585=ORIENTED_EDGE('',*,*,#1567,.F.);
#1586=ORIENTED_EDGE('',*,*,#1511,.T.);
#1587=EDGE_LOOP('',(#1559,#1568,#1577,#1584,#1585,#1586));
#1588=FACE_BOUND('',#1587,.T.);
#1589=ADVANCED_FACE('P2_F396',(#1588),#1558,.T.);
#1590=CARTESIAN_POINT('',(0.,0.5207,0.));
#1591=DIRECTION('',(0.,1.,0.));
#1592=DIRECTION('',(0.,0.,1.));
#1593=AXIS2_PLACEMENT_3D('',#1590,#1591,#1592);
#1594=CYLINDRICAL_SURFACE('',#1593,7.3152);
#1595=CARTESIAN_POINT('',(0.,1.0414,0.));
#1596=DIRECTION('',(0.,1.,0.));
#1597=DIRECTION('',(1.,0.,0.));
#1598=AXIS2_PLACEMENT_3D('',#1595,#1596,#1597);
#1599=CIRCLE('',#1598,7.3152);
#1600=CARTESIAN_POINT('',(0.,1.0414,7.3152));
#1601=VERTEX_POINT('',#1600);
#1602=CARTESIAN_POINT('',(0.,1.0414,-7.3152));
#1603=VERTEX_POINT('',#1602);
#1604=EDGE_CURVE('P2_E158',#1601,#1603,#1599,.T.);
#1605=ORIENTED_EDGE('',*,*,#1604,.T.);
#1606=DIRECTION('',(0.,-1.,0.));
#1607=VECTOR('',#1606,1.);
#1608=CARTESIAN_POINT('',(0.,0.5207,-7.3152));
#1609=LINE('',#1608,#1607);
#1610=EDGE_CURVE('P2_E154',#1603,#1566,#1609,.T.);
#1611=ORIENTED_EDGE('',*,*,#1610,.T.);
#1612=ORIENTED_EDGE('',*,*,#1583,.F.);
#1613=ORIENTED_EDGE('',*,*,#1576,.F.);
#1614=ORIENTED_EDGE('',*,*,#1610,.F.);
#1615=CARTESIAN_POINT('',(0.,1.0414,0.));
#1616=DIRECTION('',(0.,1.,0.));
#1617=DIRECTION('',(1.,0.,0.));
#1618=AXIS2_PLACEMENT_3D('',#1615,#1616,#1617);
#1619=CIRCLE('',#1618,7.3152);
#1620=EDGE_CURVE('P2_E159',#1603,#1601,#1619,.T.);
#1621=ORIENTED_EDGE('',*,*,#1620,.T.);
#1622=EDGE_LOOP('',(#1605,#1611,#1612,#1613,#1614,#1621));
#1623=FACE_BOUND('',#1622,.T.);
#1624=ADVANCED_FACE('P2_F383',(#1623),#1594,.F.);
#1625=CARTESIAN_POINT('',(0.,1.4859,0.));
#1626=DIRECTION('',(0.,-1.,0.));
#1627=DIRECTION('',(0.,0.,1.));
#1628=AXIS2_PLACEMENT_3D('',#1625,#1626,#1627);
#1629=CONICAL_SURFACE('',#1628,6.8707,0.78539816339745);
#1630=ORIENTED_EDGE('',*,*,#1295,.T.);
#1631=DIRECTION('',(0.,-0.707106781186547,-0.707106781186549));
#1632=VECTOR('',#1631,1.);
#1633=CARTESIAN_POINT('',(0.,1.4859,-6.8707));
#1634=LINE('',#1633,#1632);
#1635=EDGE_CURVE('P2_E164',#1285,#1603,#1634,.T.);
#1636=ORIENTED_EDGE('',*,*,#1635,.T.);
#1637=ORIENTED_EDGE('',*,*,#1604,.F.);
#1638=ORIENTED_EDGE('',*,*,#1620,.F.);
#1639=ORIENTED_EDGE('',*,*,#1635,.F.);
#1640=ORIENTED_EDGE('',*,*,#1302,.T.);
#1641=EDGE_LOOP('',(#1630,#1636,#1637,#1638,#1639,#1640));
#1642=FACE_BOUND('',#1641,.T.);
#1643=ADVANCED_FACE('P2_F380',(#1642),#1629,.F.);
#1644=CLOSED_SHELL('',(#1135,#1170,#1190,#1242,#1272,#1307,#1343,#1378,#1404,#1433,#1485,#1515,
#1534,#1553,#1589,#1624,#1643));
#1645=MANIFOLD_SOLID_BREP('P2_B1',#1644);
#1646=CARTESIAN_POINT('',(0.,8.40740008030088,4.9022));
#1647=DIRECTION('',(0.,-1.,0.));
#1648=DIRECTION('',(0.,0.,-1.));
#1649=AXIS2_PLACEMENT_3D('',#1646,#1647,#1648);
#1650=PLANE('',#1649);
#1651=CARTESIAN_POINT('',(0.,8.40740008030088,0.));
#1652=DIRECTION('',(0.,1.,0.));
#1653=DIRECTION('',(1.,0.,0.));
#1654=AXIS2_PLACEMENT_3D('',#1651,#1652,#1653);
#1655=CIRCLE('',#1654,4.9022);
#1656=CARTESIAN_POINT('',(0.,8.40740008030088,4.9022));
#1657=VERTEX_POINT('',#1656);
#1658=CARTESIAN_POINT('',(0.,8.40740008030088,-4.9022));
#1659=VERTEX_POINT('',#1658);
#1660=EDGE_CURVE('P3_E38',#1657,#1659,#1655,.T.);
#1661=ORIENTED_EDGE('',*,*,#1660,.F.);
#1662=CARTESIAN_POINT('',(0.,8.40740008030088,0.));
#1663=DIRECTION('',(0.,1.,0.));
#1664=DIRECTION('',(1.,0.,0.));
#1665=AXIS2_PLACEMENT_3D('',#1662,#1663,#1664);
#1666=CIRCLE('',#1665,4.9022);
#1667=EDGE_CURVE('P3_E99',#1659,#1657,#1666,.T.);
#1668=ORIENTED_EDGE('',*,*,#1667,.F.);
#1669=EDGE_LOOP('',(#1661,#1668));
#1670=FACE_BOUND('',#1669,.T.);
#1671=CARTESIAN_POINT('',(0.,8.40740008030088,0.));
#1672=DIRECTION('',(0.,1.,0.));
#1673=DIRECTION('',(1.,0.,0.));
#1674=AXIS2_PLACEMENT_3D('',#1671,#1672,#1673);
#1675=CIRCLE('',#1674,3.5052);
#1676=CARTESIAN_POINT('',(0.,8.40740008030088,3.5052));
#1677=VERTEX_POINT('',#1676);
#1678=CARTESIAN_POINT('',(0.,8.40740008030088,-3.5052));
#1679=VERTEX_POINT('',#1678);
#1680=EDGE_CURVE('P3_E10',#1677,#1679,#1675,.T.);
#1681=ORIENTED_EDGE('',*,*,#1680,.T.);
#1682=CARTESIAN_POINT('',(0.,8.40740008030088,0.));
#1683=DIRECTION('',(0.,1.,0.));
#1684=DIRECTION('',(1.,0.,0.));
#1685=AXIS2_PLACEMENT_3D('',#1682,#1683,#1684);
#1686=CIRCLE('',#1685,3.5052);
#1687=EDGE_CURVE('P3_E26',#1679,#1677,#1686,.T.);
#1688=ORIENTED_EDGE('',*,*,#1687,.T.);
#1689=EDGE_LOOP('',(#1681,#1688));
#1690=FACE_BOUND('',#1689,.T.);
#1691=ADVANCED_FACE('P3_F15',(#1670,#1690),#1650,.T.);
#1692=CARTESIAN_POINT('',(0.,10.6299000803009,0.));
#1693=DIRECTION('',(0.,1.,0.));
#1694=DIRECTION('',(0.,0.,1.));
#1695=AXIS2_PLACEMENT_3D('',#1692,#1693,#1694);
#1696=CYLINDRICAL_SURFACE('',#1695,4.9022);
#1697=CARTESIAN_POINT('',(0.,12.8524000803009,0.));
#1698=DIRECTION('',(0.,1.,0.));
#1699=DIRECTION('',(1.,0.,0.));
#1700=AXIS2_PLACEMENT_3D('',#1697,#1698,#1699);
#1701=CIRCLE('',#1700,4.9022);
#1702=CARTESIAN_POINT('',(0.,12.8524000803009,4.9022));
#1703=VERTEX_POINT('',#1702);
#1704=CARTESIAN_POINT('',(0.,12.8524000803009,-4.9022));
#1705=VERTEX_POINT('',#1704);
#1706=EDGE_CURVE('P3_E95',#1703,#1705,#1701,.T.);
#1707=ORIENTED_EDGE('',*,*,#1706,.F.);
#1708=CARTESIAN_POINT('',(0.,12.8524000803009,0.));
#1709=DIRECTION('',(0.,1.,0.));
#1710=DIRECTION('',(1.,0.,0.));
#1711=AXIS2_PLACEMENT_3D('',#1708,#1709,#1710);
#1712=CIRCLE('',#1711,4.9022);
#1713=EDGE_CURVE('P3_E53',#1705,#1703,#1712,.T.);
#1714=ORIENTED_EDGE('',*,*,#1713,.F.);
#1715=DIRECTION('',(0.,-1.,0.));
#1716=VECTOR('',#1715,1.);
#1717=CARTESIAN_POINT('',(0.,10.6299000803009,-4.9022));
#1718=LINE('',#1717,#1716);
#1719=EDGE_CURVE('P3_E19',#1705,#1659,#1718,.T.);
#1720=ORIENTED_EDGE('',*,*,#1719,.T.);
#1721=ORIENTED_EDGE('',*,*,#1667,.T.);
#1722=ORIENTED_EDGE('',*,*,#1660,.T.);
#1723=ORIENTED_EDGE('',*,*,#1719,.F.);
#1724=EDGE_LOOP('',(#1707,#1714,#1720,#1721,#1722,#1723));
#1725=FACE_BOUND('',#1724,.T.);
#1726=ADVANCED_FACE('P3_F106',(#1725),#1696,.T.);
#1727=CARTESIAN_POINT('',(0.,12.8524000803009,3.5052));
#1728=DIRECTION('',(0.,1.,0.));
#1729=DIRECTION('',(1.,0.,0.));
#1730=AXIS2_PLACEMENT_3D('',#1727,#1728,#1729);
#1731=PLANE('',#1730);
#1732=ORIENTED_EDGE('',*,*,#1706,.T.);
#1733=ORIENTED_EDGE('',*,*,#1713,.T.);
#1734=EDGE_LOOP('',(#1732,#1733));
#1735=FACE_BOUND('',#1734,.T.);
#1736=CARTESIAN_POINT('',(0.,12.8524000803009,0.));
#1737=DIRECTION('',(0.,1.,0.));
#1738=DIRECTION('',(1.,0.,0.));
#1739=AXIS2_PLACEMENT_3D('',#1736,#1737,#1738);
#1740=CIRCLE('',#1739,3.5052);
#1741=CARTESIAN_POINT('',(0.,12.8524000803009,3.5052));
#1742=VERTEX_POINT('',#1741);
#1743=CARTESIAN_POINT('',(0.,12.8524000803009,-3.5052));
#1744=VERTEX_POINT('',#1743);
#1745=EDGE_CURVE('P3_E67',#1742,#1744,#1740,.T.);
#1746=ORIENTED_EDGE('',*,*,#1745,.F.);
#1747=CARTESIAN_POINT('',(0.,12.8524000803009,0.));
#1748=DIRECTION('',(0.,1.,0.));
#1749=DIRECTION('',(1.,0.,0.));
#1750=AXIS2_PLACEMENT_3D('',#1747,#1748,#1749);
#1751=CIRCLE('',#1750,3.5052);
#1752=EDGE_CURVE('P3_E84',#1744,#1742,#1751,.T.);
#1753=ORIENTED_EDGE('',*,*,#1752,.F.);
#1754=EDGE_LOOP('',(#1746,#1753));
#1755=FACE_BOUND('',#1754,.T.);
#1756=ADVANCED_FACE('P3_F112',(#1735,#1755),#1731,.T.);
#1757=CARTESIAN_POINT('',(0.,10.6299000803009,0.));
#1758=DIRECTION('',(0.,1.,0.));
#1759=DIRECTION('',(0.,0.,1.));
#1760=AXIS2_PLACEMENT_3D('',#1757,#1758,#1759);
#1761=CYLINDRICAL_SURFACE('',#1760,3.5052);
#1762=ORIENTED_EDGE('',*,*,#1745,.T.);
#1763=DIRECTION('',(0.,-1.,0.));
#1764=VECTOR('',#1763,1.);
#1765=CARTESIAN_POINT('',(0.,10.6299000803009,-3.5052));
#1766=LINE('',#1765,#1764);
#1767=EDGE_CURVE('P3_E79',#1744,#1679,#1766,.T.);
#1768=ORIENTED_EDGE('',*,*,#1767,.T.);
#1769=ORIENTED_EDGE('',*,*,#1680,.F.);
#1770=ORIENTED_EDGE('',*,*,#1687,.F.);
#1771=ORIENTED_EDGE('',*,*,#1767,.F.);
#1772=ORIENTED_EDGE('',*,*,#1752,.T.);
#1773=EDGE_LOOP('',(#1762,#1768,#1769,#1770,#1771,#1772));
#1774=FACE_BOUND('',#1773,.T.);
#1775=ADVANCED_FACE('P3_F17',(#1774),#1761,.F.);
#1776=CLOSED_SHELL('',(#1691,#1726,#1756,#1775));
#1777=MANIFOLD_SOLID_BREP('P3_B1',#1776);
#1778=ADVANCED_BREP_SHAPE_REPRESENTATION('',(#18,#165,#1093,#1645,#1777),#14);
#1779=SHAPE_DEFINITION_REPRESENTATION(#9,#1778);
ENDSEC;
END-ISO-10303-21;
